VERSION 5.5 ;
NAMESCASESENSITIVE ON ;
BUSBITCHARS "[]" ;
DIVIDERCHAR "/" ;

PROPERTYDEFINITIONS
  LAYER routingPitch REAL ;
END PROPERTYDEFINITIONS

UNITS
  DATABASE MICRONS 1000 ;
END UNITS
MANUFACTURINGGRID 0.01 ;
LAYER POLY1
  TYPE MASTERSLICE ;
END POLY1

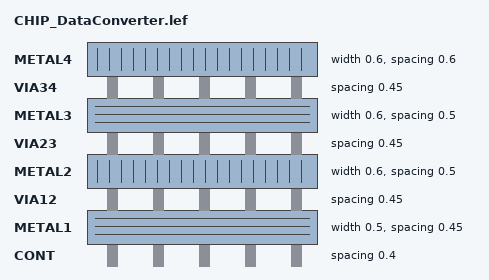
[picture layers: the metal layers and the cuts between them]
LAYER CONT
  TYPE CUT ;
  SPACING 0.4 ;
END CONT

LAYER METAL1
  TYPE ROUTING ;
  DIRECTION HORIZONTAL ;
  PITCH 0 ;
  WIDTH 0.5 ;
  SPACING 0.45 ;
  PROPERTY routingPitch 1.25 ;
END METAL1

LAYER VIA12
  TYPE CUT ;
  SPACING 0.45 ;
END VIA12

LAYER METAL2
  TYPE ROUTING ;
  DIRECTION VERTICAL ;
  PITCH 0 ;
  WIDTH 0.6 ;
  SPACING 0.5 ;
  PROPERTY routingPitch 1.4 ;
END METAL2

LAYER VIA23
  TYPE CUT ;
  SPACING 0.45 ;
END VIA23

LAYER METAL3
  TYPE ROUTING ;
  DIRECTION HORIZONTAL ;
  PITCH 0 ;
  WIDTH 0.6 ;
  SPACING 0.5 ;
  PROPERTY routingPitch 1.25 ;
END METAL3

LAYER VIA34
  TYPE CUT ;
  SPACING 0.45 ;
END VIA34

LAYER METAL4
  TYPE ROUTING ;
  DIRECTION VERTICAL ;
  PITCH 0 ;
  WIDTH 0.6 ;
  SPACING 0.6 ;
  PROPERTY routingPitch 1.4 ;
END METAL4

LAYER OVERLAP
  TYPE OVERLAP ;
END OVERLAP

VIARULE M4_M3 GENERATE
  LAYER METAL3 ;
    ENCLOSURE 0.2 0.2 ;
  LAYER METAL4 ;
    ENCLOSURE 0.15 0.15 ;
  LAYER VIA34 ;
    RECT -0.25 -0.25 0.25 0.25 ;
    SPACING 1 BY 1 ;
END M4_M3

VIARULE M3_M2 GENERATE
  LAYER METAL2 ;
    ENCLOSURE 0.2 0.2 ;
  LAYER METAL3 ;
    ENCLOSURE 0.15 0.15 ;
  LAYER VIA23 ;
    RECT -0.25 -0.25 0.25 0.25 ;
    SPACING 1 BY 1 ;
END M3_M2

VIARULE M2_M1 GENERATE
  LAYER METAL1 ;
    ENCLOSURE 0.2 0.2 ;
  LAYER METAL2 ;
    ENCLOSURE 0.15 0.15 ;
  LAYER VIA12 ;
    RECT -0.25 -0.25 0.25 0.25 ;
    SPACING 1 BY 1 ;
END M2_M1

VIARULE M1_POLY1 GENERATE
  LAYER POLY1 ;
    ENCLOSURE 0.2 0.2 ;
  LAYER METAL1 ;
    ENCLOSURE 0.15 0.15 ;
  LAYER CONT ;
    RECT -0.2 -0.2 0.2 0.2 ;
    SPACING 1 BY 1 ;
END M1_POLY1

VIA M1_POLY1
  LAYER CONT ;
    RECT -0.2 -0.2 0.2 0.2 ;
  LAYER POLY1 ;
    RECT -0.4 -0.4 0.4 0.4 ;
  LAYER METAL1 ;
    RECT -0.35 -0.35 0.35 0.35 ;
END M1_POLY1

VIA M2_M1
  LAYER VIA12 ;
    RECT -0.25 -0.25 0.25 0.25 ;
  LAYER METAL2 ;
    RECT -0.4 -0.4 0.4 0.4 ;
  LAYER METAL1 ;
    RECT -0.45 -0.45 0.45 0.45 ;
END M2_M1

VIA M3_M2
  LAYER VIA23 ;
    RECT -0.25 -0.25 0.25 0.25 ;
  LAYER METAL3 ;
    RECT -0.4 -0.4 0.4 0.4 ;
  LAYER METAL2 ;
    RECT -0.45 -0.45 0.45 0.45 ;
END M3_M2

VIA M4_M3
  LAYER VIA34 ;
    RECT -0.25 -0.25 0.25 0.25 ;
  LAYER METAL4 ;
    RECT -0.4 -0.4 0.4 0.4 ;
  LAYER METAL3 ;
    RECT -0.45 -0.45 0.45 0.45 ;
END M4_M3


MACRO Full_Macro_Edit
  PIN SystemDrainline<1>
    DIRECTION INOUT ;
    USE SIGNAL ;
    PORT
      LAYER METAL3 ;
        RECT 6312.6 1412.6 6314.0 1414.0 ;
    END
  END SystemDrainline<1>
  PIN SystemDrainline<2>
    DIRECTION INOUT ;
    USE SIGNAL ;
    PORT
      LAYER METAL3 ;
        RECT 6312.6 943.6 6314.0 945.0 ;
    END
  END SystemDrainline<2>
  PIN sram_CS_VBIAS
    DIRECTION INOUT ;
    USE SIGNAL ;
    PORT
      LAYER METAL3 ;
        RECT 0.0 2.8 1.4 4.2 ;
    END
  END sram_CS_VBIAS
  PIN drain_pulse_rst
    DIRECTION INOUT ;
    USE SIGNAL ;
    PORT
      LAYER METAL3 ;
        RECT 6312.6 1.4 6314.0 2.8 ;
    END
  END drain_pulse_rst
  PIN fast_ADC_clk
    DIRECTION INOUT ;
    USE SIGNAL ;
    PORT
      LAYER METAL3 ;
        RECT 6312.6 471.8 6314.0 473.2 ;
    END
  END fast_ADC_clk
  PIN peri_spi_slave_RX_DV
    DIRECTION INOUT ;
    USE SIGNAL ;
    PORT
      LAYER METAL3 ;
        RECT 0.0 1412.6 1.4 1414.0 ;
    END
  END peri_spi_slave_RX_DV
  PIN peri_spi_mstr_RX_DV
    DIRECTION INOUT ;
    USE SIGNAL ;
    PORT
      LAYER METAL3 ;
        RECT 0.0 1330.0 1.4 1331.4 ;
    END
  END peri_spi_mstr_RX_DV
  PIN peri_spi_mstr_TX_Ready
    DIRECTION INOUT ;
    USE SIGNAL ;
    PORT
      LAYER METAL3 ;
        RECT 0.0 1247.4 1.4 1248.8 ;
    END
  END peri_spi_mstr_TX_Ready
  PIN peri_spi_mstr_cs_n_3
    DIRECTION INOUT ;
    USE SIGNAL ;
    PORT
      LAYER METAL3 ;
        RECT 0.0 1163.4 1.4 1164.8 ;
    END
  END peri_spi_mstr_cs_n_3
  PIN peri_spi_mstr_cs_n_2
    DIRECTION INOUT ;
    USE SIGNAL ;
    PORT
      LAYER METAL3 ;
        RECT 0.0 1080.8 1.4 1082.2 ;
    END
  END peri_spi_mstr_cs_n_2
  PIN peri_spi_mstr_cs_n_1
    DIRECTION INOUT ;
    USE SIGNAL ;
    PORT
      LAYER METAL3 ;
        RECT 0.0 996.8 1.4 998.2 ;
    END
  END peri_spi_mstr_cs_n_1
  PIN peri_spi_mstr_cs_n_0
    DIRECTION INOUT ;
    USE SIGNAL ;
    PORT
      LAYER METAL3 ;
        RECT 0.0 914.2 1.4 915.6 ;
    END
  END peri_spi_mstr_cs_n_0
  PIN peri_spi_mstr_mosi
    DIRECTION INOUT ;
    USE SIGNAL ;
    PORT
      LAYER METAL3 ;
        RECT 0.0 830.2 1.4 831.6 ;
    END
  END peri_spi_mstr_mosi
  PIN peri_spi_mstr_spiclk
    DIRECTION INOUT ;
    USE SIGNAL ;
    PORT
      LAYER METAL3 ;
        RECT 0.0 664.7 0.6 665.3 ;
    END
  END peri_spi_mstr_spiclk
  PIN peri_spi_slave_miso
    DIRECTION INOUT ;
    USE SIGNAL ;
    PORT
      LAYER METAL3 ;
        RECT 0.0 415.8 1.4 417.2 ;
    END
  END peri_spi_slave_miso
  PIN peri_spi_mstr_miso
    DIRECTION INOUT ;
    USE SIGNAL ;
    PORT
      LAYER METAL3 ;
        RECT 0.0 747.6 1.4 749.0 ;
    END
  END peri_spi_mstr_miso
  PIN peri_spi_slave_cs_n
    DIRECTION INOUT ;
    USE SIGNAL ;
    PORT
      LAYER METAL3 ;
        RECT 0.0 582.4 1.4 583.8 ;
    END
  END peri_spi_slave_cs_n
  PIN peri_spi_slave_mosi
    DIRECTION INOUT ;
    USE SIGNAL ;
    PORT
      LAYER METAL3 ;
        RECT 0.0 498.4 1.4 499.8 ;
    END
  END peri_spi_slave_mosi
  PIN peri_spi_slave_clk
    DIRECTION INOUT ;
    USE SIGNAL ;
    PORT
      LAYER METAL3 ;
        RECT 0.0 331.8 1.4 333.2 ;
    END
  END peri_spi_slave_clk
  PIN peri_spi_cpu_clk
    DIRECTION INOUT ;
    USE SIGNAL ;
    PORT
      LAYER METAL3 ;
        RECT 0.0 249.2 1.4 250.6 ;
    END
  END peri_spi_cpu_clk
  PIN peri_spi_rst
    DIRECTION INOUT ;
    USE SIGNAL ;
    PORT
      LAYER METAL3 ;
        RECT 0.0 165.2 1.4 166.6 ;
    END
  END peri_spi_rst
  PIN peri_use_uP
    DIRECTION INOUT ;
    USE SIGNAL ;
    PORT
      LAYER METAL3 ;
        RECT 0.0 82.6 1.4 84.0 ;
    END
  END peri_use_uP
  PIN irq_acc<12>
    DIRECTION INOUT ;
    USE SIGNAL ;
    PORT
      LAYER METAL2 ;
        RECT 894.6 0.0 896.0 1.4 ;
    END
  END irq_acc<12>
  PIN irq_acc<13>
    DIRECTION INOUT ;
    USE SIGNAL ;
    PORT
      LAYER METAL2 ;
        RECT 834.4 0.0 835.8 1.4 ;
    END
  END irq_acc<13>
  PIN irq<0>
    DIRECTION INOUT ;
    USE SIGNAL ;
    PORT
      LAYER METAL2 ;
        RECT 774.2 0.0 775.6 1.4 ;
    END
  END irq<0>
  PIN irq<1>
    DIRECTION INOUT ;
    USE SIGNAL ;
    PORT
      LAYER METAL2 ;
        RECT 715.4 0.0 716.8 1.4 ;
    END
  END irq<1>
  PIN irq<2>
    DIRECTION INOUT ;
    USE SIGNAL ;
    PORT
      LAYER METAL2 ;
        RECT 655.2 0.0 656.6 1.4 ;
    END
  END irq<2>
  PIN irq<3>
    DIRECTION INOUT ;
    USE SIGNAL ;
    PORT
      LAYER METAL2 ;
        RECT 596.4 0.0 597.8 1.4 ;
    END
  END irq<3>
  PIN irq<4>
    DIRECTION INOUT ;
    USE SIGNAL ;
    PORT
      LAYER METAL2 ;
        RECT 536.2 0.0 537.6 1.4 ;
    END
  END irq<4>
  PIN irq<5>
    DIRECTION INOUT ;
    USE SIGNAL ;
    PORT
      LAYER METAL2 ;
        RECT 477.4 0.0 478.8 1.4 ;
    END
  END irq<5>
  PIN irq<6>
    DIRECTION INOUT ;
    USE SIGNAL ;
    PORT
      LAYER METAL2 ;
        RECT 417.2 0.0 418.6 1.4 ;
    END
  END irq<6>
  PIN irq<7>
    DIRECTION INOUT ;
    USE SIGNAL ;
    PORT
      LAYER METAL2 ;
        RECT 358.4 0.0 359.8 1.4 ;
    END
  END irq<7>
  PIN irq<8>
    DIRECTION INOUT ;
    USE SIGNAL ;
    PORT
      LAYER METAL2 ;
        RECT 298.2 0.0 299.6 1.4 ;
    END
  END irq<8>
  PIN irq<9>
    DIRECTION INOUT ;
    USE SIGNAL ;
    PORT
      LAYER METAL2 ;
        RECT 239.4 0.0 240.8 1.4 ;
    END
  END irq<9>
  PIN irq<10>
    DIRECTION INOUT ;
    USE SIGNAL ;
    PORT
      LAYER METAL2 ;
        RECT 179.2 0.0 180.6 1.4 ;
    END
  END irq<10>
  PIN irq<11>
    DIRECTION INOUT ;
    USE SIGNAL ;
    PORT
      LAYER METAL2 ;
        RECT 119.0 0.0 120.4 1.4 ;
    END
  END irq<11>
  PIN irq<12>
    DIRECTION INOUT ;
    USE SIGNAL ;
    PORT
      LAYER METAL2 ;
        RECT 60.2 0.0 61.6 1.4 ;
    END
  END irq<12>
  PIN irq<13>
    DIRECTION INOUT ;
    USE SIGNAL ;
    PORT
      LAYER METAL2 ;
        RECT 1.4 0.0 2.8 1.4 ;
    END
  END irq<13>
  PIN irq_acc<1>
    DIRECTION INOUT ;
    USE SIGNAL ;
    PORT
      LAYER METAL2 ;
        RECT 1548.4 0.0 1549.8 1.4 ;
    END
  END irq_acc<1>
  PIN irq_acc<2>
    DIRECTION INOUT ;
    USE SIGNAL ;
    PORT
      LAYER METAL2 ;
        RECT 1489.6 0.0 1491.0 1.4 ;
    END
  END irq_acc<2>
  PIN irq_acc<3>
    DIRECTION INOUT ;
    USE SIGNAL ;
    PORT
      LAYER METAL2 ;
        RECT 1429.4 0.0 1430.8 1.4 ;
    END
  END irq_acc<3>
  PIN irq_acc<4>
    DIRECTION INOUT ;
    USE SIGNAL ;
    PORT
      LAYER METAL2 ;
        RECT 1370.6 0.0 1372.0 1.4 ;
    END
  END irq_acc<4>
  PIN irq_acc<5>
    DIRECTION INOUT ;
    USE SIGNAL ;
    PORT
      LAYER METAL2 ;
        RECT 1310.4 0.0 1311.8 1.4 ;
    END
  END irq_acc<5>
  PIN irq_acc<6>
    DIRECTION INOUT ;
    USE SIGNAL ;
    PORT
      LAYER METAL2 ;
        RECT 1251.6 0.0 1253.0 1.4 ;
    END
  END irq_acc<6>
  PIN irq_acc<7>
    DIRECTION INOUT ;
    USE SIGNAL ;
    PORT
      LAYER METAL2 ;
        RECT 1191.4 0.0 1192.8 1.4 ;
    END
  END irq_acc<7>
  PIN irq_acc<8>
    DIRECTION INOUT ;
    USE SIGNAL ;
    PORT
      LAYER METAL2 ;
        RECT 1132.6 0.0 1134.0 1.4 ;
    END
  END irq_acc<8>
  PIN irq_acc<9>
    DIRECTION INOUT ;
    USE SIGNAL ;
    PORT
      LAYER METAL2 ;
        RECT 1072.4 0.0 1073.8 1.4 ;
    END
  END irq_acc<9>
  PIN irq_acc<10>
    DIRECTION INOUT ;
    USE SIGNAL ;
    PORT
      LAYER METAL2 ;
        RECT 1013.6 0.0 1015.0 1.4 ;
    END
  END irq_acc<10>
  PIN irq_acc<11>
    DIRECTION INOUT ;
    USE SIGNAL ;
    PORT
      LAYER METAL2 ;
        RECT 953.4 0.0 954.8 1.4 ;
    END
  END irq_acc<11>
  PIN irq_acc<0>
    DIRECTION INOUT ;
    USE SIGNAL ;
    PORT
      LAYER METAL2 ;
        RECT 1608.6 0.0 1610.0 1.4 ;
    END
  END irq_acc<0>
  PIN mmio_reg_4_vinj_out<1>
    DIRECTION INOUT ;
    USE SIGNAL ;
    PORT
      LAYER METAL2 ;
        RECT 1906.8 0.0 1908.2 1.4 ;
    END
  END mmio_reg_4_vinj_out<1>
  PIN mmio_reg_4_vinj_out<2>
    DIRECTION INOUT ;
    USE SIGNAL ;
    PORT
      LAYER METAL2 ;
        RECT 1846.6 0.0 1848.0 1.4 ;
    END
  END mmio_reg_4_vinj_out<2>
  PIN mmio_reg_4_vinj_out<3>
    DIRECTION INOUT ;
    USE SIGNAL ;
    PORT
      LAYER METAL2 ;
        RECT 1787.8 0.0 1789.2 1.4 ;
    END
  END mmio_reg_4_vinj_out<3>
  PIN mmio_reg_4_vinj_out<4>
    DIRECTION INOUT ;
    USE SIGNAL ;
    PORT
      LAYER METAL2 ;
        RECT 1727.6 0.0 1729.0 1.4 ;
    END
  END mmio_reg_4_vinj_out<4>
  PIN mmio_reg_4_vinj_out<5>
    DIRECTION INOUT ;
    USE SIGNAL ;
    PORT
      LAYER METAL2 ;
        RECT 1668.8 0.0 1670.2 1.4 ;
    END
  END mmio_reg_4_vinj_out<5>
  PIN mmio_reg_4_vinj_out<0>
    DIRECTION INOUT ;
    USE SIGNAL ;
    PORT
      LAYER METAL2 ;
        RECT 1965.6 0.0 1967.0 1.4 ;
    END
  END mmio_reg_4_vinj_out<0>
  PIN mmio_reg_3_vinj_out<10>
    DIRECTION INOUT ;
    USE SIGNAL ;
    PORT
      LAYER METAL2 ;
        RECT 2322.6 0.0 2324.0 1.4 ;
    END
  END mmio_reg_3_vinj_out<10>
  PIN mmio_reg_3_vinj_out<11>
    DIRECTION INOUT ;
    USE SIGNAL ;
    PORT
      LAYER METAL2 ;
        RECT 2263.8 0.0 2265.2 1.4 ;
    END
  END mmio_reg_3_vinj_out<11>
  PIN mmio_reg_3_vinj_out<12>
    DIRECTION INOUT ;
    USE SIGNAL ;
    PORT
      LAYER METAL2 ;
        RECT 2203.6 0.0 2205.0 1.4 ;
    END
  END mmio_reg_3_vinj_out<12>
  PIN mmio_reg_3_vinj_out<13>
    DIRECTION INOUT ;
    USE SIGNAL ;
    PORT
      LAYER METAL2 ;
        RECT 2144.8 0.0 2146.2 1.4 ;
    END
  END mmio_reg_3_vinj_out<13>
  PIN mmio_reg_3_vinj_out<14>
    DIRECTION INOUT ;
    USE SIGNAL ;
    PORT
      LAYER METAL2 ;
        RECT 2084.6 0.0 2086.0 1.4 ;
    END
  END mmio_reg_3_vinj_out<14>
  PIN mmio_reg_3_vinj_out<15>
    DIRECTION INOUT ;
    USE SIGNAL ;
    PORT
      LAYER METAL2 ;
        RECT 2025.8 0.0 2027.2 1.4 ;
    END
  END mmio_reg_3_vinj_out<15>
  PIN mmio_reg_1_out<0>
    DIRECTION INOUT ;
    USE SIGNAL ;
    PORT
      LAYER METAL2 ;
        RECT 2501.8 0.0 2503.2 1.4 ;
    END
  END mmio_reg_1_out<0>
  PIN mmio_reg_1_out<1>
    DIRECTION INOUT ;
    USE SIGNAL ;
    PORT
      LAYER METAL2 ;
        RECT 2562.0 0.0 2563.4 1.4 ;
    END
  END mmio_reg_1_out<1>
  PIN mmio_reg_in_5<9>
    DIRECTION INOUT ;
    USE SIGNAL ;
    PORT
      LAYER METAL2 ;
        RECT 2977.8 0.0 2979.2 1.4 ;
    END
  END mmio_reg_in_5<9>
  PIN mmio_reg_in_5<10>
    DIRECTION INOUT ;
    USE SIGNAL ;
    PORT
      LAYER METAL2 ;
        RECT 2919.0 0.0 2920.4 1.4 ;
    END
  END mmio_reg_in_5<10>
  PIN mmio_reg_in_5<11>
    DIRECTION INOUT ;
    USE SIGNAL ;
    PORT
      LAYER METAL2 ;
        RECT 2858.8 0.0 2860.2 1.4 ;
    END
  END mmio_reg_in_5<11>
  PIN mmio_reg_in_5<12>
    DIRECTION INOUT ;
    USE SIGNAL ;
    PORT
      LAYER METAL2 ;
        RECT 2800.0 0.0 2801.4 1.4 ;
    END
  END mmio_reg_in_5<12>
  PIN mmio_reg_in_5<13>
    DIRECTION INOUT ;
    USE SIGNAL ;
    PORT
      LAYER METAL2 ;
        RECT 2739.8 0.0 2741.2 1.4 ;
    END
  END mmio_reg_in_5<13>
  PIN mmio_reg_in_5<14>
    DIRECTION INOUT ;
    USE SIGNAL ;
    PORT
      LAYER METAL2 ;
        RECT 2681.0 0.0 2682.4 1.4 ;
    END
  END mmio_reg_in_5<14>
  PIN mmio_reg_in_5<15>
    DIRECTION INOUT ;
    USE SIGNAL ;
    PORT
      LAYER METAL2 ;
        RECT 2620.8 0.0 2622.2 1.4 ;
    END
  END mmio_reg_in_5<15>
  PIN mmio_reg_in_5<2>
    DIRECTION INOUT ;
    USE SIGNAL ;
    PORT
      LAYER METAL2 ;
        RECT 3395.0 0.0 3396.4 1.4 ;
    END
  END mmio_reg_in_5<2>
  PIN mmio_reg_in_5<3>
    DIRECTION INOUT ;
    USE SIGNAL ;
    PORT
      LAYER METAL2 ;
        RECT 3336.2 0.0 3337.6 1.4 ;
    END
  END mmio_reg_in_5<3>
  PIN mmio_reg_in_5<4>
    DIRECTION INOUT ;
    USE SIGNAL ;
    PORT
      LAYER METAL2 ;
        RECT 3276.0 0.0 3277.4 1.4 ;
    END
  END mmio_reg_in_5<4>
  PIN mmio_reg_in_5<5>
    DIRECTION INOUT ;
    USE SIGNAL ;
    PORT
      LAYER METAL2 ;
        RECT 3217.2 0.0 3218.6 1.4 ;
    END
  END mmio_reg_in_5<5>
  PIN mmio_reg_in_5<6>
    DIRECTION INOUT ;
    USE SIGNAL ;
    PORT
      LAYER METAL2 ;
        RECT 3157.0 0.0 3158.4 1.4 ;
    END
  END mmio_reg_in_5<6>
  PIN mmio_reg_in_5<7>
    DIRECTION INOUT ;
    USE SIGNAL ;
    PORT
      LAYER METAL2 ;
        RECT 3096.8 0.0 3098.2 1.4 ;
    END
  END mmio_reg_in_5<7>
  PIN mmio_reg_in_5<8>
    DIRECTION INOUT ;
    USE SIGNAL ;
    PORT
      LAYER METAL2 ;
        RECT 3038.0 0.0 3039.4 1.4 ;
    END
  END mmio_reg_in_5<8>
  PIN mmio_reg_10<11>
    DIRECTION INOUT ;
    USE SIGNAL ;
    PORT
      LAYER METAL2 ;
        RECT 3812.2 0.0 3813.6 1.4 ;
    END
  END mmio_reg_10<11>
  PIN mmio_reg_10<12>
    DIRECTION INOUT ;
    USE SIGNAL ;
    PORT
      LAYER METAL2 ;
        RECT 3752.0 0.0 3753.4 1.4 ;
    END
  END mmio_reg_10<12>
  PIN mmio_reg_10<13>
    DIRECTION INOUT ;
    USE SIGNAL ;
    PORT
      LAYER METAL2 ;
        RECT 3693.2 0.0 3694.6 1.4 ;
    END
  END mmio_reg_10<13>
  PIN mmio_reg_10<14>
    DIRECTION INOUT ;
    USE SIGNAL ;
    PORT
      LAYER METAL2 ;
        RECT 3633.0 0.0 3634.4 1.4 ;
    END
  END mmio_reg_10<14>
  PIN mmio_reg_10<15>
    DIRECTION INOUT ;
    USE SIGNAL ;
    PORT
      LAYER METAL2 ;
        RECT 3574.2 0.0 3575.6 1.4 ;
    END
  END mmio_reg_10<15>
  PIN mmio_reg_in_5<0>
    DIRECTION INOUT ;
    USE SIGNAL ;
    PORT
      LAYER METAL2 ;
        RECT 3514.0 0.0 3515.4 1.4 ;
    END
  END mmio_reg_in_5<0>
  PIN mmio_reg_in_5<1>
    DIRECTION INOUT ;
    USE SIGNAL ;
    PORT
      LAYER METAL2 ;
        RECT 3455.2 0.0 3456.6 1.4 ;
    END
  END mmio_reg_in_5<1>
  PIN mmio_reg_10<4>
    DIRECTION INOUT ;
    USE SIGNAL ;
    PORT
      LAYER METAL2 ;
        RECT 4229.4 0.0 4230.8 1.4 ;
    END
  END mmio_reg_10<4>
  PIN mmio_reg_10<5>
    DIRECTION INOUT ;
    USE SIGNAL ;
    PORT
      LAYER METAL2 ;
        RECT 4169.2 0.0 4170.6 1.4 ;
    END
  END mmio_reg_10<5>
  PIN mmio_reg_10<6>
    DIRECTION INOUT ;
    USE SIGNAL ;
    PORT
      LAYER METAL2 ;
        RECT 4110.4 0.0 4111.8 1.4 ;
    END
  END mmio_reg_10<6>
  PIN mmio_reg_10<7>
    DIRECTION INOUT ;
    USE SIGNAL ;
    PORT
      LAYER METAL2 ;
        RECT 4050.2 0.0 4051.6 1.4 ;
    END
  END mmio_reg_10<7>
  PIN mmio_reg_10<8>
    DIRECTION INOUT ;
    USE SIGNAL ;
    PORT
      LAYER METAL2 ;
        RECT 3991.4 0.0 3992.8 1.4 ;
    END
  END mmio_reg_10<8>
  PIN mmio_reg_10<9>
    DIRECTION INOUT ;
    USE SIGNAL ;
    PORT
      LAYER METAL2 ;
        RECT 3931.2 0.0 3932.6 1.4 ;
    END
  END mmio_reg_10<9>
  PIN mmio_reg_10<10>
    DIRECTION INOUT ;
    USE SIGNAL ;
    PORT
      LAYER METAL2 ;
        RECT 3871.0 0.0 3872.4 1.4 ;
    END
  END mmio_reg_10<10>
  PIN mmio_reg_10<0>
    DIRECTION INOUT ;
    USE SIGNAL ;
    PORT
      LAYER METAL2 ;
        RECT 4467.4 0.0 4468.8 1.4 ;
    END
  END mmio_reg_10<0>
  PIN mmio_reg_10<1>
    DIRECTION INOUT ;
    USE SIGNAL ;
    PORT
      LAYER METAL2 ;
        RECT 4407.2 0.0 4408.6 1.4 ;
    END
  END mmio_reg_10<1>
  PIN mmio_reg_10<2>
    DIRECTION INOUT ;
    USE SIGNAL ;
    PORT
      LAYER METAL2 ;
        RECT 4348.4 0.0 4349.8 1.4 ;
    END
  END mmio_reg_10<2>
  PIN mmio_reg_10<3>
    DIRECTION INOUT ;
    USE SIGNAL ;
    PORT
      LAYER METAL2 ;
        RECT 4288.2 0.0 4289.6 1.4 ;
    END
  END mmio_reg_10<3>
  PIN mmio_reg_2_out_b15
    DIRECTION INOUT ;
    USE SIGNAL ;
    PORT
      LAYER METAL2 ;
        RECT 2382.8 0.0 2384.2 1.4 ;
    END
  END mmio_reg_2_out_b15
  PIN mmio_reg_9_out_b15
    DIRECTION INOUT ;
    USE SIGNAL ;
    PORT
      LAYER METAL2 ;
        RECT 2443.0 0.0 2444.4 1.4 ;
    END
  END mmio_reg_9_out_b15
  PIN Signal_DAC_out[0]
    DIRECTION INOUT ;
    USE SIGNAL ;
    PORT
      LAYER METAL2 ;
        RECT 5360.6 0.0 5362.0 1.4 ;
    END
  END Signal_DAC_out[0]
  PIN Signal_DAC_out[1]
    DIRECTION INOUT ;
    USE SIGNAL ;
    PORT
      LAYER METAL2 ;
        RECT 5300.4 0.0 5301.8 1.4 ;
    END
  END Signal_DAC_out[1]
  PIN Signal_DAC_out[2]
    DIRECTION INOUT ;
    USE SIGNAL ;
    PORT
      LAYER METAL2 ;
        RECT 5241.6 0.0 5243.0 1.4 ;
    END
  END Signal_DAC_out[2]
  PIN Signal_DAC_out[3]
    DIRECTION INOUT ;
    USE SIGNAL ;
    PORT
      LAYER METAL2 ;
        RECT 5181.4 0.0 5182.8 1.4 ;
    END
  END Signal_DAC_out[3]
  PIN Signal_DAC_out[4]
    DIRECTION INOUT ;
    USE SIGNAL ;
    PORT
      LAYER METAL2 ;
        RECT 5122.6 0.0 5124.0 1.4 ;
    END
  END Signal_DAC_out[4]
  PIN Signal_ADC_inp[0]
    DIRECTION INOUT ;
    USE SIGNAL ;
    PORT
      LAYER METAL2 ;
        RECT 5717.6 0.0 5719.0 1.4 ;
    END
  END Signal_ADC_inp[0]
  PIN Signal_ADC_inp[1]
    DIRECTION INOUT ;
    USE SIGNAL ;
    PORT
      LAYER METAL2 ;
        RECT 5658.8 0.0 5660.2 1.4 ;
    END
  END Signal_ADC_inp[1]
  PIN Signal_ADC_inp[2]
    DIRECTION INOUT ;
    USE SIGNAL ;
    PORT
      LAYER METAL2 ;
        RECT 5598.6 0.0 5600.0 1.4 ;
    END
  END Signal_ADC_inp[2]
  PIN Signal_ADC_inp[3]
    DIRECTION INOUT ;
    USE SIGNAL ;
    PORT
      LAYER METAL2 ;
        RECT 5539.8 0.0 5541.2 1.4 ;
    END
  END Signal_ADC_inp[3]
  PIN Signal_ADC_inp[4]
    DIRECTION INOUT ;
    USE SIGNAL ;
    PORT
      LAYER METAL2 ;
        RECT 5479.6 0.0 5481.0 1.4 ;
    END
  END Signal_ADC_inp[4]
  PIN Signal_ADC_inp[5]
    DIRECTION INOUT ;
    USE SIGNAL ;
    PORT
      LAYER METAL2 ;
        RECT 5419.4 0.0 5420.8 1.4 ;
    END
  END Signal_ADC_inp[5]
  PIN VGPROG_IO
    DIRECTION INOUT ;
    USE SIGNAL ;
    PORT
      LAYER METAL2 ;
        RECT 5955.6 0.0 5957.0 1.4 ;
    END
  END VGPROG_IO
  PIN VTUN_AM
    DIRECTION INOUT ;
    USE SIGNAL ;
    PORT
      LAYER METAL2 ;
        RECT 6074.6 0.0 6076.0 1.4 ;
    END
  END VTUN_AM
  PIN AVDD_AM
    DIRECTION INOUT ;
    USE SIGNAL ;
    PORT
      LAYER METAL2 ;
        RECT 6193.6 0.0 6195.0 1.4 ;
    END
  END AVDD_AM
  PIN V_IO
    DIRECTION INOUT ;
    USE SIGNAL ;
    PORT
      LAYER METAL2 ;
        RECT 4526.2 0.0 4527.6 1.4 ;
    END
  END V_IO
  PIN VG_IO
    DIRECTION INOUT ;
    USE SIGNAL ;
    PORT
      LAYER METAL2 ;
        RECT 4586.4 0.0 4587.8 1.4 ;
    END
  END VG_IO
  PIN VGRUN
    DIRECTION INOUT ;
    USE SIGNAL ;
    PORT
      LAYER METAL2 ;
        RECT 4645.2 0.0 4646.6 1.4 ;
    END
  END VGRUN
  PIN VD_IO
    DIRECTION INOUT ;
    USE SIGNAL ;
    PORT
      LAYER METAL2 ;
        RECT 4705.4 0.0 4706.8 1.4 ;
    END
  END VD_IO
  PIN I_IO
    DIRECTION INOUT ;
    USE SIGNAL ;
    PORT
      LAYER METAL2 ;
        RECT 4765.6 0.0 4767.0 1.4 ;
    END
  END I_IO
  PIN Debug_IO
    DIRECTION INOUT ;
    USE SIGNAL ;
    PORT
      LAYER METAL2 ;
        RECT 4824.4 0.0 4825.8 1.4 ;
    END
  END Debug_IO
  PIN Cal_Vin
    DIRECTION INOUT ;
    USE SIGNAL ;
    PORT
      LAYER METAL2 ;
        RECT 4884.6 0.0 4886.0 1.4 ;
    END
  END Cal_Vin
  PIN Cal_IO
    DIRECTION INOUT ;
    USE SIGNAL ;
    PORT
      LAYER METAL2 ;
        RECT 4943.4 0.0 4944.8 1.4 ;
    END
  END Cal_IO
  PIN Bias_Trim
    DIRECTION INOUT ;
    USE SIGNAL ;
    PORT
      LAYER METAL2 ;
        RECT 5003.6 0.0 5005.0 1.4 ;
    END
  END Bias_Trim
  PIN ADC_Trim
    DIRECTION INOUT ;
    USE SIGNAL ;
    PORT
      LAYER METAL2 ;
        RECT 5062.4 0.0 5063.8 1.4 ;
    END
  END ADC_Trim
  PIN run
    DIRECTION INOUT ;
    USE SIGNAL ;
    PORT
      LAYER METAL2 ;
        RECT 5777.8 0.0 5779.2 1.4 ;
    END
  END run
  PIN prog
    DIRECTION INOUT ;
    USE SIGNAL ;
    PORT
      LAYER METAL2 ;
        RECT 5836.6 0.0 5838.0 1.4 ;
    END
  END prog
  PIN fgmem_CS_VBIAS
    DIRECTION INOUT ;
    USE SIGNAL ;
    PORT
      LAYER METAL2 ;
        RECT 5896.8 0.0 5898.2 1.4 ;
    END
  END fgmem_CS_VBIAS
  PIN VTUN_fgmem
    DIRECTION INOUT ;
    USE SIGNAL ;
    PORT
      LAYER METAL2 ;
        RECT 6015.8 0.0 6017.2 1.4 ;
    END
  END VTUN_fgmem
  PIN VINJ
    DIRECTION INOUT ;
    USE SIGNAL ;
    PORT
      LAYER METAL2 ;
        RECT 6134.8 0.0 6136.2 1.4 ;
    END
  END VINJ
  PIN GND
    DIRECTION INOUT ;
    USE SIGNAL ;
    PORT
      LAYER METAL2 ;
        RECT 6253.8 0.0 6255.2 1.4 ;
    END
  END GND
  PIN DVDD
    DIRECTION INOUT ;
    USE SIGNAL ;
    PORT
      LAYER METAL2 ;
        RECT 6311.2 0.0 6312.6 1.4 ;
    END
  END DVDD
  PIN scan_out2
    DIRECTION INOUT ;
    USE SIGNAL ;
    PORT
      LAYER METAL2 ;
        RECT 3682.0 1414.0 3683.4 1415.4 ;
    END
  END scan_out2
  PIN scan_in2
    DIRECTION INOUT ;
    USE SIGNAL ;
    PORT
      LAYER METAL2 ;
        RECT 3155.6 1414.0 3157.0 1415.4 ;
    END
  END scan_in2
  PIN scan_out1
    DIRECTION INOUT ;
    USE SIGNAL ;
    PORT
      LAYER METAL2 ;
        RECT 3418.8 1414.0 3420.2 1415.4 ;
    END
  END scan_out1
  PIN scan_in1
    DIRECTION INOUT ;
    USE SIGNAL ;
    PORT
      LAYER METAL2 ;
        RECT 2892.4 1414.0 2893.8 1415.4 ;
    END
  END scan_in1
  PIN wkup
    DIRECTION INOUT ;
    USE SIGNAL ;
    PORT
      LAYER METAL2 ;
        RECT 2629.2 1414.0 2630.6 1415.4 ;
    END
  END wkup
  PIN scan_mode
    DIRECTION INOUT ;
    USE SIGNAL ;
    PORT
      LAYER METAL2 ;
        RECT 2366.0 1414.0 2367.4 1415.4 ;
    END
  END scan_mode
  PIN scan_enable
    DIRECTION INOUT ;
    USE SIGNAL ;
    PORT
      LAYER METAL2 ;
        RECT 2104.2 1414.0 2105.6 1415.4 ;
    END
  END scan_enable
  PIN reset_n
    DIRECTION INOUT ;
    USE SIGNAL ;
    PORT
      LAYER METAL2 ;
        RECT 1841.0 1414.0 1842.4 1415.4 ;
    END
  END reset_n
  PIN nmi
    DIRECTION INOUT ;
    USE SIGNAL ;
    PORT
      LAYER METAL2 ;
        RECT 1577.8 1414.0 1579.2 1415.4 ;
    END
  END nmi
  PIN lfxt_clk
    DIRECTION INOUT ;
    USE SIGNAL ;
    PORT
      LAYER METAL2 ;
        RECT 1314.61 1414.0 1316.0 1415.4 ;
    END
  END lfxt_clk
  PIN dco_clk
    DIRECTION INOUT ;
    USE SIGNAL ;
    PORT
      LAYER METAL2 ;
        RECT 1051.4 1414.0 1052.8 1415.4 ;
    END
  END dco_clk
  PIN dbg_uart_rxd
    DIRECTION INOUT ;
    USE SIGNAL ;
    PORT
      LAYER METAL2 ;
        RECT 525.0 1414.0 526.4 1415.4 ;
    END
  END dbg_uart_rxd
  PIN dbg_en
    DIRECTION INOUT ;
    USE SIGNAL ;
    PORT
      LAYER METAL2 ;
        RECT 261.8 1414.0 263.2 1415.4 ;
    END
  END dbg_en
  PIN cpu_en
    DIRECTION INOUT ;
    USE SIGNAL ;
    PORT
      LAYER METAL2 ;
        RECT 1.4 1414.0 2.8 1415.4 ;
    END
  END cpu_en
  PIN smclk_en
    DIRECTION INOUT ;
    USE SIGNAL ;
    PORT
      LAYER METAL2 ;
        RECT 6309.8 1414.0 6311.2 1415.4 ;
    END
  END smclk_en
  PIN smclk
    DIRECTION INOUT ;
    USE SIGNAL ;
    PORT
      LAYER METAL2 ;
        RECT 6049.4 1414.0 6050.8 1415.4 ;
    END
  END smclk
  PIN mclk
    DIRECTION INOUT ;
    USE SIGNAL ;
    PORT
      LAYER METAL2 ;
        RECT 5786.2 1414.0 5787.6 1415.4 ;
    END
  END mclk
  PIN lfxt_wkup
    DIRECTION INOUT ;
    USE SIGNAL ;
    PORT
      LAYER METAL2 ;
        RECT 5523.0 1414.0 5524.4 1415.4 ;
    END
  END lfxt_wkup
  PIN lfxt_enable
    DIRECTION INOUT ;
    USE SIGNAL ;
    PORT
      LAYER METAL2 ;
        RECT 5259.8 1414.0 5261.2 1415.4 ;
    END
  END lfxt_enable
  PIN dco_wkup
    DIRECTION INOUT ;
    USE SIGNAL ;
    PORT
      LAYER METAL2 ;
        RECT 4996.6 1414.0 4998.0 1415.4 ;
    END
  END dco_wkup
  PIN dco_enable
    DIRECTION INOUT ;
    USE SIGNAL ;
    PORT
      LAYER METAL2 ;
        RECT 4733.4 1414.0 4734.8 1415.4 ;
    END
  END dco_enable
  PIN dbg_uart_txd
    DIRECTION INOUT ;
    USE SIGNAL ;
    PORT
      LAYER METAL2 ;
        RECT 788.2 1414.0 789.6 1415.4 ;
    END
  END dbg_uart_txd
  PIN dbg_freeze
    DIRECTION INOUT ;
    USE SIGNAL ;
    PORT
      LAYER METAL2 ;
        RECT 4470.2 1414.0 4471.6 1415.4 ;
    END
  END dbg_freeze
  PIN aclk_en
    DIRECTION INOUT ;
    USE SIGNAL ;
    PORT
      LAYER METAL2 ;
        RECT 4208.4 1414.0 4209.8 1415.4 ;
    END
  END aclk_en
  PIN aclk
    DIRECTION INOUT ;
    USE SIGNAL ;
    PORT
      LAYER METAL2 ;
        RECT 3945.2 1414.0 3946.6 1415.4 ;
    END
  END aclk
END Full_Macro_Edit

MACRO QDAC_synth
  PIN n_VGRUN
    DIRECTION INOUT ;
    USE SIGNAL ;
    PORT
      LAYER METAL3 ;
        RECT 55.3 246.7 56.7 249.5 ;
    END
  END n_VGRUN
  PIN w_GateB<0>
    DIRECTION INOUT ;
    USE SIGNAL ;
    PORT
      LAYER METAL3 ;
        RECT 0.0 234.1 2.8 235.5 ;
    END
  END w_GateB<0>
  PIN w_GateB<1>
    DIRECTION INOUT ;
    USE SIGNAL ;
    PORT
      LAYER METAL3 ;
        RECT 0.0 220.1 2.8 221.5 ;
    END
  END w_GateB<1>
  PIN n_Code<4>
    DIRECTION INOUT ;
    USE SIGNAL ;
    PORT
      LAYER METAL3 ;
        RECT 167.3 246.7 168.7 249.5 ;
    END
  END n_Code<4>
  PIN n_Code<0>
    DIRECTION INOUT ;
    USE SIGNAL ;
    PORT
      LAYER METAL3 ;
        RECT 111.3 246.7 112.7 249.5 ;
    END
  END n_Code<0>
  PIN n_VGPROG
    DIRECTION INOUT ;
    USE SIGNAL ;
    PORT
      LAYER METAL3 ;
        RECT 41.3 246.7 42.7 249.5 ;
    END
  END n_VGPROG
  PIN s_vinj
    DIRECTION INOUT ;
    USE SIGNAL ;
    PORT
      LAYER METAL3 ;
        RECT 192.41 0.0 193.81 2.8 ;
    END
  END s_vinj
  PIN n_Code<2>
    DIRECTION INOUT ;
    USE SIGNAL ;
    PORT
      LAYER METAL3 ;
        RECT 139.3 246.7 140.7 249.5 ;
    END
  END n_Code<2>
  PIN n_Code<3>
    DIRECTION INOUT ;
    USE SIGNAL ;
    PORT
      LAYER METAL3 ;
        RECT 153.3 246.7 154.7 249.5 ;
    END
  END n_Code<3>
  PIN w_DrainEnable
    DIRECTION INOUT ;
    USE SIGNAL ;
    PORT
      LAYER METAL3 ;
        RECT 0.0 150.1 2.8 151.5 ;
    END
  END w_DrainEnable
  PIN n_Code<1>
    DIRECTION INOUT ;
    USE SIGNAL ;
    PORT
      LAYER METAL3 ;
        RECT 125.3 246.7 126.7 249.5 ;
    END
  END n_Code<1>
  PIN n_RST
    DIRECTION INOUT ;
    USE SIGNAL ;
    PORT
      LAYER METAL3 ;
        RECT 97.3 246.7 98.7 249.5 ;
    END
  END n_RST
  PIN n_gnd
    DIRECTION INOUT ;
    USE SIGNAL ;
    PORT
      LAYER METAL3 ;
        RECT 206.41 246.7 207.81 249.5 ;
    END
  END n_gnd
  PIN s_gnd
    DIRECTION INOUT ;
    USE SIGNAL ;
    PORT
      LAYER METAL3 ;
        RECT 206.41 0.0 207.81 2.8 ;
    END
  END s_gnd
  PIN s_Run_Drainline
    DIRECTION INOUT ;
    USE SIGNAL ;
    PORT
      LAYER METAL3 ;
        RECT 13.3 0.0 14.7 2.8 ;
    END
  END s_Run_Drainline
  PIN s_Vout
    DIRECTION INOUT ;
    USE SIGNAL ;
    PORT
      LAYER METAL3 ;
        RECT 41.3 0.0 42.7 2.8 ;
    END
  END s_Vout
  PIN n_vinj
    DIRECTION INOUT ;
    USE SIGNAL ;
    PORT
      LAYER METAL3 ;
        RECT 192.41 246.7 193.81 249.5 ;
    END
  END n_vinj
  PIN w_DrainB<1>
    DIRECTION INOUT ;
    USE SIGNAL ;
    PORT
      LAYER METAL3 ;
        RECT 0.0 192.1 2.8 193.5 ;
    END
  END w_DrainB<1>
  PIN w_DrainB<3>
    DIRECTION INOUT ;
    USE SIGNAL ;
    PORT
      LAYER METAL3 ;
        RECT 0.0 164.1 2.8 165.5 ;
    END
  END w_DrainB<3>
  PIN s_Prog_Drainline
    DIRECTION INOUT ;
    USE SIGNAL ;
    PORT
      LAYER METAL3 ;
        RECT 27.3 0.0 28.7 2.8 ;
    END
  END s_Prog_Drainline
  PIN n_Run
    DIRECTION INOUT ;
    USE SIGNAL ;
    PORT
      LAYER METAL3 ;
        RECT 27.3 246.7 28.7 249.5 ;
    END
  END n_Run
  PIN w_DrainB<2>
    DIRECTION INOUT ;
    USE SIGNAL ;
    PORT
      LAYER METAL3 ;
        RECT 0.0 178.1 2.8 179.5 ;
    END
  END w_DrainB<2>
  PIN n_VTUN
    DIRECTION INOUT ;
    USE SIGNAL ;
    PORT
      LAYER METAL3 ;
        RECT 69.3 246.7 70.7 249.5 ;
    END
  END n_VTUN
  PIN n_GateEnable
    DIRECTION INOUT ;
    USE SIGNAL ;
    PORT
      LAYER METAL3 ;
        RECT 83.3 246.7 84.7 249.5 ;
    END
  END n_GateEnable
  PIN n_avdd
    DIRECTION INOUT ;
    USE SIGNAL ;
    PORT
      LAYER METAL3 ;
        RECT 220.41 246.7 221.81 249.5 ;
    END
  END n_avdd
  PIN s_avdd
    DIRECTION INOUT ;
    USE SIGNAL ;
    PORT
      LAYER METAL3 ;
        RECT 220.41 0.0 221.81 2.8 ;
    END
  END s_avdd
  PIN n_Prog
    DIRECTION INOUT ;
    USE SIGNAL ;
    PORT
      LAYER METAL3 ;
        RECT 13.3 246.7 14.7 249.5 ;
    END
  END n_Prog
  PIN w_DrainB<0>
    DIRECTION INOUT ;
    USE SIGNAL ;
    PORT
      LAYER METAL3 ;
        RECT 0.0 206.1 2.8 207.5 ;
    END
  END w_DrainB<0>
END QDAC_synth

MACRO RampADC_synth
  PIN n_gnd
    DIRECTION INOUT ;
    USE SIGNAL ;
    PORT
      LAYER METAL3 ;
        RECT 274.04 141.6 275.44 144.4 ;
    END
  END n_gnd
  PIN s_gnd
    DIRECTION INOUT ;
    USE SIGNAL ;
    PORT
      LAYER METAL3 ;
        RECT 274.04 0.0 275.44 2.8 ;
    END
  END s_gnd
  PIN n_vinj
    DIRECTION INOUT ;
    USE SIGNAL ;
    PORT
      LAYER METAL3 ;
        RECT 260.04 141.6 261.44 144.4 ;
    END
  END n_vinj
  PIN s_vinj
    DIRECTION INOUT ;
    USE SIGNAL ;
    PORT
      LAYER METAL3 ;
        RECT 260.04 0.0 261.44 2.8 ;
    END
  END s_vinj
  PIN n_avdd
    DIRECTION INOUT ;
    USE SIGNAL ;
    PORT
      LAYER METAL3 ;
        RECT 246.04 141.6 247.44 144.4 ;
    END
  END n_avdd
  PIN s_avdd
    DIRECTION INOUT ;
    USE SIGNAL ;
    PORT
      LAYER METAL3 ;
        RECT 246.04 0.0 247.44 2.8 ;
    END
  END s_avdd
  PIN s_Code<7>
    DIRECTION INOUT ;
    USE SIGNAL ;
    PORT
      LAYER METAL3 ;
        RECT 139.3 0.0 140.7 2.8 ;
    END
  END s_Code<7>
  PIN s_Code<6>
    DIRECTION INOUT ;
    USE SIGNAL ;
    PORT
      LAYER METAL3 ;
        RECT 125.3 0.0 126.7 2.8 ;
    END
  END s_Code<6>
  PIN s_Code<5>
    DIRECTION INOUT ;
    USE SIGNAL ;
    PORT
      LAYER METAL3 ;
        RECT 111.3 0.0 112.7 2.8 ;
    END
  END s_Code<5>
  PIN s_Code<4>
    DIRECTION INOUT ;
    USE SIGNAL ;
    PORT
      LAYER METAL3 ;
        RECT 97.3 0.0 98.7 2.8 ;
    END
  END s_Code<4>
  PIN n_GateEnable
    DIRECTION INOUT ;
    USE SIGNAL ;
    PORT
      LAYER METAL3 ;
        RECT 83.3 141.6 84.7 144.4 ;
    END
  END n_GateEnable
  PIN s_Code<3>
    DIRECTION INOUT ;
    USE SIGNAL ;
    PORT
      LAYER METAL3 ;
        RECT 83.3 0.0 84.7 2.8 ;
    END
  END s_Code<3>
  PIN s_Code<2>
    DIRECTION INOUT ;
    USE SIGNAL ;
    PORT
      LAYER METAL3 ;
        RECT 69.3 0.0 70.7 2.8 ;
    END
  END s_Code<2>
  PIN n_VTUN
    DIRECTION INOUT ;
    USE SIGNAL ;
    PORT
      LAYER METAL3 ;
        RECT 69.3 141.6 70.7 144.4 ;
    END
  END n_VTUN
  PIN s_Code<1>
    DIRECTION INOUT ;
    USE SIGNAL ;
    PORT
      LAYER METAL3 ;
        RECT 55.3 0.0 56.7 2.8 ;
    END
  END s_Code<1>
  PIN n_VGPROG
    DIRECTION INOUT ;
    USE SIGNAL ;
    PORT
      LAYER METAL3 ;
        RECT 55.3 141.6 56.7 144.4 ;
    END
  END n_VGPROG
  PIN s_Code<0>
    DIRECTION INOUT ;
    USE SIGNAL ;
    PORT
      LAYER METAL3 ;
        RECT 41.3 0.0 42.7 2.8 ;
    END
  END s_Code<0>
  PIN n_VGRUN
    DIRECTION INOUT ;
    USE SIGNAL ;
    PORT
      LAYER METAL3 ;
        RECT 41.3 141.6 42.7 144.4 ;
    END
  END n_VGRUN
  PIN s_Prog_Drainline
    DIRECTION INOUT ;
    USE SIGNAL ;
    PORT
      LAYER METAL3 ;
        RECT 27.3 0.0 28.7 2.8 ;
    END
  END s_Prog_Drainline
  PIN n_Run
    DIRECTION INOUT ;
    USE SIGNAL ;
    PORT
      LAYER METAL3 ;
        RECT 27.3 141.6 28.7 144.4 ;
    END
  END n_Run
  PIN s_Run_Drainline
    DIRECTION INOUT ;
    USE SIGNAL ;
    PORT
      LAYER METAL3 ;
        RECT 13.3 0.0 14.7 2.8 ;
    END
  END s_Run_Drainline
  PIN n_Prog
    DIRECTION INOUT ;
    USE SIGNAL ;
    PORT
      LAYER METAL3 ;
        RECT 13.3 141.6 14.7 144.4 ;
    END
  END n_Prog
  PIN w_DrainEnable
    DIRECTION INOUT ;
    USE SIGNAL ;
    PORT
      LAYER METAL3 ;
        RECT 0.0 101.0 2.8 102.4 ;
    END
  END w_DrainEnable
  PIN w_DrainB<0>
    DIRECTION INOUT ;
    USE SIGNAL ;
    PORT
      LAYER METAL3 ;
        RECT 0.0 129.0 2.8 130.4 ;
    END
  END w_DrainB<0>
  PIN w_DrainB<1>
    DIRECTION INOUT ;
    USE SIGNAL ;
    PORT
      LAYER METAL3 ;
        RECT 0.0 115.0 2.8 116.4 ;
    END
  END w_DrainB<1>
  PIN w_GateB<0>
    DIRECTION INOUT ;
    USE SIGNAL ;
    PORT
      LAYER METAL3 ;
        RECT 0.0 87.0 2.8 88.4 ;
    END
  END w_GateB<0>
  PIN w_GateB<1>
    DIRECTION INOUT ;
    USE SIGNAL ;
    PORT
      LAYER METAL3 ;
        RECT 0.0 73.0 2.8 74.4 ;
    END
  END w_GateB<1>
  PIN w_CLK
    DIRECTION INOUT ;
    USE SIGNAL ;
    PORT
      LAYER METAL3 ;
        RECT 0.0 59.0 2.8 60.4 ;
    END
  END w_CLK
  PIN w_RST
    DIRECTION INOUT ;
    USE SIGNAL ;
    PORT
      LAYER METAL3 ;
        RECT 0.0 45.0 2.8 46.4 ;
    END
  END w_RST
  PIN w_Vin
    DIRECTION INOUT ;
    USE SIGNAL ;
    PORT
      LAYER METAL3 ;
        RECT 0.0 31.0 2.8 32.4 ;
    END
  END w_Vin
END RampADC_synth

MACRO AlgorithmicADC_synth
  PIN n_vinj
    DIRECTION INOUT ;
    USE SIGNAL ;
    PORT
      LAYER METAL3 ;
        RECT 208.91 217.6 210.31 220.4 ;
    END
  END n_vinj
  PIN n_RUN
    DIRECTION INOUT ;
    USE SIGNAL ;
    PORT
      LAYER METAL3 ;
        RECT 27.3 217.6 28.7 220.4 ;
    END
  END n_RUN
  PIN n_avdd
    DIRECTION INOUT ;
    USE SIGNAL ;
    PORT
      LAYER METAL3 ;
        RECT 194.91 217.6 196.31 220.4 ;
    END
  END n_avdd
  PIN n_VTUN
    DIRECTION INOUT ;
    USE SIGNAL ;
    PORT
      LAYER METAL3 ;
        RECT 69.3 217.6 70.7 220.4 ;
    END
  END n_VTUN
  PIN n_PROG
    DIRECTION INOUT ;
    USE SIGNAL ;
    PORT
      LAYER METAL3 ;
        RECT 13.3 217.6 14.7 220.4 ;
    END
  END n_PROG
  PIN n_VGRUN
    DIRECTION INOUT ;
    USE SIGNAL ;
    PORT
      LAYER METAL3 ;
        RECT 41.3 217.6 42.7 220.4 ;
    END
  END n_VGRUN
  PIN n_VGPROG
    DIRECTION INOUT ;
    USE SIGNAL ;
    PORT
      LAYER METAL3 ;
        RECT 55.3 217.6 56.7 220.4 ;
    END
  END n_VGPROG
  PIN n_GateEnable
    DIRECTION INOUT ;
    USE SIGNAL ;
    PORT
      LAYER METAL3 ;
        RECT 83.3 217.6 84.7 220.4 ;
    END
  END n_GateEnable
  PIN n_gnd
    DIRECTION INOUT ;
    USE SIGNAL ;
    PORT
      LAYER METAL3 ;
        RECT 222.91 217.6 224.31 220.4 ;
    END
  END n_gnd
  PIN w_DrainB<0>
    DIRECTION INOUT ;
    USE SIGNAL ;
    PORT
      LAYER METAL3 ;
        RECT 0.0 205.0 2.8 206.4 ;
    END
  END w_DrainB<0>
  PIN e_CLK_Sample
    DIRECTION INOUT ;
    USE SIGNAL ;
    PORT
      LAYER METAL3 ;
        RECT 249.51 205.0 252.31 206.4 ;
    END
  END e_CLK_Sample
  PIN w_DrainB<1>
    DIRECTION INOUT ;
    USE SIGNAL ;
    PORT
      LAYER METAL3 ;
        RECT 0.0 191.0 2.8 192.4 ;
    END
  END w_DrainB<1>
  PIN e_CLK_Amp
    DIRECTION INOUT ;
    USE SIGNAL ;
    PORT
      LAYER METAL3 ;
        RECT 249.51 191.0 252.31 192.4 ;
    END
  END e_CLK_Amp
  PIN w_DrainB<2>
    DIRECTION INOUT ;
    USE SIGNAL ;
    PORT
      LAYER METAL3 ;
        RECT 0.0 177.0 2.8 178.4 ;
    END
  END w_DrainB<2>
  PIN e_CLK_Load
    DIRECTION INOUT ;
    USE SIGNAL ;
    PORT
      LAYER METAL3 ;
        RECT 249.51 177.0 252.31 178.4 ;
    END
  END e_CLK_Load
  PIN w_DrainB<3>
    DIRECTION INOUT ;
    USE SIGNAL ;
    PORT
      LAYER METAL3 ;
        RECT 0.0 163.0 2.8 164.4 ;
    END
  END w_DrainB<3>
  PIN w_DrainEnable
    DIRECTION INOUT ;
    USE SIGNAL ;
    PORT
      LAYER METAL3 ;
        RECT 0.0 149.0 2.8 150.4 ;
    END
  END w_DrainEnable
  PIN w_GateB<0>
    DIRECTION INOUT ;
    USE SIGNAL ;
    PORT
      LAYER METAL3 ;
        RECT 0.0 135.0 2.8 136.4 ;
    END
  END w_GateB<0>
  PIN w_GateB<1>
    DIRECTION INOUT ;
    USE SIGNAL ;
    PORT
      LAYER METAL3 ;
        RECT 0.0 121.0 2.8 122.4 ;
    END
  END w_GateB<1>
  PIN w_VIN
    DIRECTION INOUT ;
    USE SIGNAL ;
    PORT
      LAYER METAL3 ;
        RECT 0.0 107.0 2.8 108.4 ;
    END
  END w_VIN
  PIN s_Drainline_Run
    DIRECTION INOUT ;
    USE SIGNAL ;
    PORT
      LAYER METAL3 ;
        RECT 27.3 0.0 28.7 2.8 ;
    END
  END s_Drainline_Run
  PIN s_vinj
    DIRECTION INOUT ;
    USE SIGNAL ;
    PORT
      LAYER METAL3 ;
        RECT 208.91 0.0 210.31 2.8 ;
    END
  END s_vinj
  PIN s_Drainline_Prog
    DIRECTION INOUT ;
    USE SIGNAL ;
    PORT
      LAYER METAL3 ;
        RECT 13.3 0.0 14.7 2.8 ;
    END
  END s_Drainline_Prog
  PIN s_avdd
    DIRECTION INOUT ;
    USE SIGNAL ;
    PORT
      LAYER METAL3 ;
        RECT 194.91 0.0 196.31 2.8 ;
    END
  END s_avdd
  PIN s_VRES
    DIRECTION INOUT ;
    USE SIGNAL ;
    PORT
      LAYER METAL3 ;
        RECT 55.3 0.0 56.7 2.8 ;
    END
  END s_VRES
  PIN s_CLK_RST
    DIRECTION INOUT ;
    USE SIGNAL ;
    PORT
      LAYER METAL3 ;
        RECT 41.3 0.0 42.7 2.8 ;
    END
  END s_CLK_RST
  PIN s_gnd
    DIRECTION INOUT ;
    USE SIGNAL ;
    PORT
      LAYER METAL3 ;
        RECT 222.91 0.0 224.31 2.8 ;
    END
  END s_gnd
END AlgorithmicADC_synth

MACRO AveragerDAC_synth
  PIN w_GateB<0>
    DIRECTION INOUT ;
    USE SIGNAL ;
    PORT
      LAYER METAL3 ;
        RECT 0.0 168.0 2.8 169.4 ;
    END
  END w_GateB<0>
  PIN n_vinj
    DIRECTION INOUT ;
    USE SIGNAL ;
    PORT
      LAYER METAL3 ;
        RECT 161.03 250.6 162.43 253.4 ;
    END
  END n_vinj
  PIN n_gnd
    DIRECTION INOUT ;
    USE SIGNAL ;
    PORT
      LAYER METAL3 ;
        RECT 175.03 250.6 176.43 253.4 ;
    END
  END n_gnd
  PIN n_VGRUN
    DIRECTION INOUT ;
    USE SIGNAL ;
    PORT
      LAYER METAL3 ;
        RECT 41.3 250.6 42.7 253.4 ;
    END
  END n_VGRUN
  PIN w_DrainEnable
    DIRECTION INOUT ;
    USE SIGNAL ;
    PORT
      LAYER METAL3 ;
        RECT 0.0 182.0 2.8 183.4 ;
    END
  END w_DrainEnable
  PIN w_GateB<1>
    DIRECTION INOUT ;
    USE SIGNAL ;
    PORT
      LAYER METAL3 ;
        RECT 0.0 154.0 2.8 155.4 ;
    END
  END w_GateB<1>
  PIN e_Code<3>
    DIRECTION INOUT ;
    USE SIGNAL ;
    PORT
      LAYER METAL3 ;
        RECT 215.63 196.0 218.43 197.4 ;
    END
  END e_Code<3>
  PIN n_VGPROG
    DIRECTION INOUT ;
    USE SIGNAL ;
    PORT
      LAYER METAL3 ;
        RECT 55.3 250.6 56.7 253.4 ;
    END
  END n_VGPROG
  PIN e_Code<4>
    DIRECTION INOUT ;
    USE SIGNAL ;
    PORT
      LAYER METAL3 ;
        RECT 215.63 182.0 218.43 183.4 ;
    END
  END e_Code<4>
  PIN w_DrainB<3>
    DIRECTION INOUT ;
    USE SIGNAL ;
    PORT
      LAYER METAL3 ;
        RECT 0.0 196.0 2.8 197.4 ;
    END
  END w_DrainB<3>
  PIN e_Code<2>
    DIRECTION INOUT ;
    USE SIGNAL ;
    PORT
      LAYER METAL3 ;
        RECT 215.63 210.0 218.43 211.4 ;
    END
  END e_Code<2>
  PIN e_Code<1>
    DIRECTION INOUT ;
    USE SIGNAL ;
    PORT
      LAYER METAL3 ;
        RECT 215.63 224.0 218.43 225.4 ;
    END
  END e_Code<1>
  PIN e_Code<0>
    DIRECTION INOUT ;
    USE SIGNAL ;
    PORT
      LAYER METAL3 ;
        RECT 215.63 238.0 218.43 239.4 ;
    END
  END e_Code<0>
  PIN w_DrainB<1>
    DIRECTION INOUT ;
    USE SIGNAL ;
    PORT
      LAYER METAL3 ;
        RECT 0.0 224.0 2.8 225.4 ;
    END
  END w_DrainB<1>
  PIN n_Prog
    DIRECTION INOUT ;
    USE SIGNAL ;
    PORT
      LAYER METAL3 ;
        RECT 13.3 250.6 14.7 253.4 ;
    END
  END n_Prog
  PIN n_GateEnable
    DIRECTION INOUT ;
    USE SIGNAL ;
    PORT
      LAYER METAL3 ;
        RECT 83.3 250.6 84.7 253.4 ;
    END
  END n_GateEnable
  PIN n_Run
    DIRECTION INOUT ;
    USE SIGNAL ;
    PORT
      LAYER METAL3 ;
        RECT 27.3 250.6 28.7 253.4 ;
    END
  END n_Run
  PIN s_gnd
    DIRECTION INOUT ;
    USE SIGNAL ;
    PORT
      LAYER METAL3 ;
        RECT 175.03 0.0 176.43 2.8 ;
    END
  END s_gnd
  PIN s_Vout
    DIRECTION INOUT ;
    USE SIGNAL ;
    PORT
      LAYER METAL3 ;
        RECT 41.3 0.0 42.7 2.8 ;
    END
  END s_Vout
  PIN w_DrainB<2>
    DIRECTION INOUT ;
    USE SIGNAL ;
    PORT
      LAYER METAL3 ;
        RECT 0.0 210.0 2.8 211.4 ;
    END
  END w_DrainB<2>
  PIN w_DrainB<0>
    DIRECTION INOUT ;
    USE SIGNAL ;
    PORT
      LAYER METAL3 ;
        RECT 0.0 238.0 2.8 239.4 ;
    END
  END w_DrainB<0>
  PIN n_VTUN
    DIRECTION INOUT ;
    USE SIGNAL ;
    PORT
      LAYER METAL3 ;
        RECT 69.3 250.6 70.7 253.4 ;
    END
  END n_VTUN
  PIN n_avdd
    DIRECTION INOUT ;
    USE SIGNAL ;
    PORT
      LAYER METAL3 ;
        RECT 189.03 250.6 190.43 253.4 ;
    END
  END n_avdd
  PIN s_avdd
    DIRECTION INOUT ;
    USE SIGNAL ;
    PORT
      LAYER METAL3 ;
        RECT 189.03 0.0 190.43 2.8 ;
    END
  END s_avdd
  PIN s_Prog_Drainline
    DIRECTION INOUT ;
    USE SIGNAL ;
    PORT
      LAYER METAL3 ;
        RECT 27.3 0.0 28.7 2.8 ;
    END
  END s_Prog_Drainline
  PIN s_vinj
    DIRECTION INOUT ;
    USE SIGNAL ;
    PORT
      LAYER METAL3 ;
        RECT 161.03 0.0 162.43 2.8 ;
    END
  END s_vinj
  PIN s_Run_Drainline
    DIRECTION INOUT ;
    USE SIGNAL ;
    PORT
      LAYER METAL3 ;
        RECT 13.3 0.0 14.7 2.8 ;
    END
  END s_Run_Drainline
END AveragerDAC_synth

MACRO frame_6p9mm_2mm_edit
  PIN gnd_E<1>
    DIRECTION INOUT ;
    USE SIGNAL ;
    PORT
      LAYER METAL2 ;
        RECT 6705.1 1243.55 6705.9 1251.35 ;
    END
  END gnd_E<1>
  PIN gnd_E<0>
    DIRECTION INOUT ;
    USE SIGNAL ;
    PORT
      LAYER METAL2 ;
        RECT 6705.1 1561.55 6705.9 1569.35 ;
    END
  END gnd_E<0>
  PIN gnd_S<2>
    DIRECTION INOUT ;
    USE SIGNAL ;
    PORT
      LAYER METAL2 ;
        RECT 6202.1 217.55 6209.9 218.35 ;
    END
  END gnd_S<2>
  PIN esd_vdd_S<2>
    DIRECTION INOUT ;
    USE SIGNAL ;
    PORT
      LAYER METAL2 ;
        RECT 6308.1 217.56 6315.9 218.35 ;
    END
  END esd_vdd_S<2>
  PIN avdd_S<2>
    DIRECTION INOUT ;
    USE SIGNAL ;
    PORT
      LAYER METAL2 ;
        RECT 6414.1 217.55 6421.9 218.35 ;
    END
  END avdd_S<2>
  PIN VINJ_S<2>
    DIRECTION INOUT ;
    USE SIGNAL ;
    PORT
      LAYER METAL2 ;
        RECT 6520.1 217.55 6527.9 218.35 ;
    END
  END VINJ_S<2>
  PIN esd_vdd_S<1>
    DIRECTION INOUT ;
    USE SIGNAL ;
    PORT
      LAYER METAL2 ;
        RECT 3340.1 217.56 3347.9 218.35 ;
    END
  END esd_vdd_S<1>
  PIN avdd_S<1>
    DIRECTION INOUT ;
    USE SIGNAL ;
    PORT
      LAYER METAL2 ;
        RECT 3446.1 217.55 3453.9 218.35 ;
    END
  END avdd_S<1>
  PIN VINJ_S<1>
    DIRECTION INOUT ;
    USE SIGNAL ;
    PORT
      LAYER METAL2 ;
        RECT 3552.1 217.55 3559.9 218.35 ;
    END
  END VINJ_S<1>
  PIN gnd_S<1>
    DIRECTION INOUT ;
    USE SIGNAL ;
    PORT
      LAYER METAL2 ;
        RECT 3234.1 217.55 3241.9 218.35 ;
    END
  END gnd_S<1>
  PIN VINJ_S<0>
    DIRECTION INOUT ;
    USE SIGNAL ;
    PORT
      LAYER METAL2 ;
        RECT 584.1 217.55 591.9 218.35 ;
    END
  END VINJ_S<0>
  PIN avdd_S<0>
    DIRECTION INOUT ;
    USE SIGNAL ;
    PORT
      LAYER METAL2 ;
        RECT 478.1 217.55 485.9 218.35 ;
    END
  END avdd_S<0>
  PIN esd_vdd_S<0>
    DIRECTION INOUT ;
    USE SIGNAL ;
    PORT
      LAYER METAL2 ;
        RECT 372.1 217.56 379.9 218.35 ;
    END
  END esd_vdd_S<0>
  PIN gnd_S<0>
    DIRECTION INOUT ;
    USE SIGNAL ;
    PORT
      LAYER METAL2 ;
        RECT 266.1 217.55 273.9 218.35 ;
    END
  END gnd_S<0>
  PIN VINJ_N<2>
    DIRECTION INOUT ;
    USE SIGNAL ;
    PORT
      LAYER METAL2 ;
        RECT 6520.1 1852.55 6527.9 1853.35 ;
    END
  END VINJ_N<2>
  PIN avdd_N<2>
    DIRECTION INOUT ;
    USE SIGNAL ;
    PORT
      LAYER METAL2 ;
        RECT 6414.1 1852.55 6421.9 1853.35 ;
    END
  END avdd_N<2>
  PIN esd_vdd_N<2>
    DIRECTION INOUT ;
    USE SIGNAL ;
    PORT
      LAYER METAL2 ;
        RECT 6308.1 1852.55 6315.9 1853.35 ;
    END
  END esd_vdd_N<2>
  PIN gnd_N<8>
    DIRECTION INOUT ;
    USE SIGNAL ;
    PORT
      LAYER METAL2 ;
        RECT 6202.1 1852.55 6209.9 1853.35 ;
    END
  END gnd_N<8>
  PIN gnd_N<7>
    DIRECTION INOUT ;
    USE SIGNAL ;
    PORT
      LAYER METAL2 ;
        RECT 5990.1 1852.55 5997.9 1853.35 ;
    END
  END gnd_N<7>
  PIN gnd_N<6>
    DIRECTION INOUT ;
    USE SIGNAL ;
    PORT
      LAYER METAL2 ;
        RECT 3976.1 1852.55 3983.9 1853.35 ;
    END
  END gnd_N<6>
  PIN gnd_N<5>
    DIRECTION INOUT ;
    USE SIGNAL ;
    PORT
      LAYER METAL2 ;
        RECT 3764.1 1852.55 3771.9 1853.35 ;
    END
  END gnd_N<5>
  PIN VINJ_N<1>
    DIRECTION INOUT ;
    USE SIGNAL ;
    PORT
      LAYER METAL2 ;
        RECT 3552.1 1852.55 3559.9 1853.35 ;
    END
  END VINJ_N<1>
  PIN avdd_N<1>
    DIRECTION INOUT ;
    USE SIGNAL ;
    PORT
      LAYER METAL2 ;
        RECT 3446.1 1852.55 3453.9 1853.35 ;
    END
  END avdd_N<1>
  PIN esd_vdd_N<1>
    DIRECTION INOUT ;
    USE SIGNAL ;
    PORT
      LAYER METAL2 ;
        RECT 3340.1 1852.55 3347.9 1853.35 ;
    END
  END esd_vdd_N<1>
  PIN gnd_N<4>
    DIRECTION INOUT ;
    USE SIGNAL ;
    PORT
      LAYER METAL2 ;
        RECT 3234.1 1852.55 3241.9 1853.35 ;
    END
  END gnd_N<4>
  PIN gnd_N<3>
    DIRECTION INOUT ;
    USE SIGNAL ;
    PORT
      LAYER METAL2 ;
        RECT 3022.1 1852.55 3029.9 1853.35 ;
    END
  END gnd_N<3>
  PIN gnd_N<2>
    DIRECTION INOUT ;
    USE SIGNAL ;
    PORT
      LAYER METAL2 ;
        RECT 1008.1 1852.55 1015.9 1853.35 ;
    END
  END gnd_N<2>
  PIN gnd_N<1>
    DIRECTION INOUT ;
    USE SIGNAL ;
    PORT
      LAYER METAL2 ;
        RECT 796.1 1852.55 803.9 1853.35 ;
    END
  END gnd_N<1>
  PIN VINJ_N<0>
    DIRECTION INOUT ;
    USE SIGNAL ;
    PORT
      LAYER METAL2 ;
        RECT 584.1 1852.55 591.9 1853.35 ;
    END
  END VINJ_N<0>
  PIN avdd_N<0>
    DIRECTION INOUT ;
    USE SIGNAL ;
    PORT
      LAYER METAL2 ;
        RECT 478.1 1852.55 485.9 1853.35 ;
    END
  END avdd_N<0>
  PIN esd_vdd_N<0>
    DIRECTION INOUT ;
    USE SIGNAL ;
    PORT
      LAYER METAL2 ;
        RECT 372.1 1852.56 379.9 1853.35 ;
    END
  END esd_vdd_N<0>
  PIN gnd_N<0>
    DIRECTION INOUT ;
    USE SIGNAL ;
    PORT
      LAYER METAL2 ;
        RECT 266.11 1852.55 273.9 1853.35 ;
    END
  END gnd_N<0>
  PIN gnd_W<1>
    DIRECTION INOUT ;
    USE SIGNAL ;
    PORT
      LAYER METAL2 ;
        RECT 194.1 1243.55 194.9 1251.35 ;
    END
  END gnd_W<1>
  PIN gnd_W<0>
    DIRECTION INOUT ;
    USE SIGNAL ;
    PORT
      LAYER METAL2 ;
        RECT 194.1 1561.55 194.9 1569.35 ;
    END
  END gnd_W<0>
  PIN IO_E<8>
    DIRECTION INOUT ;
    USE SIGNAL ;
    PORT
      LAYER METAL2 ;
        RECT 6705.1 289.55 6705.9 297.35 ;
    END
  END IO_E<8>
  PIN IO_E<7>
    DIRECTION INOUT ;
    USE SIGNAL ;
    PORT
      LAYER METAL2 ;
        RECT 6705.1 395.55 6705.9 403.35 ;
    END
  END IO_E<7>
  PIN IO_E<6>
    DIRECTION INOUT ;
    USE SIGNAL ;
    PORT
      LAYER METAL2 ;
        RECT 6705.1 501.55 6705.9 509.35 ;
    END
  END IO_E<6>
  PIN IO_E<5>
    DIRECTION INOUT ;
    USE SIGNAL ;
    PORT
      LAYER METAL2 ;
        RECT 6705.1 607.55 6705.9 615.35 ;
    END
  END IO_E<5>
  PIN IO_E<4>
    DIRECTION INOUT ;
    USE SIGNAL ;
    PORT
      LAYER METAL2 ;
        RECT 6705.1 713.55 6705.9 721.35 ;
    END
  END IO_E<4>
  PIN IO_E<3>
    DIRECTION INOUT ;
    USE SIGNAL ;
    PORT
      LAYER METAL2 ;
        RECT 6705.1 819.55 6705.9 827.35 ;
    END
  END IO_E<3>
  PIN IO_E<2>
    DIRECTION INOUT ;
    USE SIGNAL ;
    PORT
      LAYER METAL2 ;
        RECT 6705.1 925.55 6705.9 933.35 ;
    END
  END IO_E<2>
  PIN IO_E<1>
    DIRECTION INOUT ;
    USE SIGNAL ;
    PORT
      LAYER METAL2 ;
        RECT 6705.1 1031.55 6705.9 1039.35 ;
    END
  END IO_E<1>
  PIN IO_E<0>
    DIRECTION INOUT ;
    USE SIGNAL ;
    PORT
      LAYER METAL2 ;
        RECT 6705.1 1137.55 6705.9 1145.35 ;
    END
  END IO_E<0>
  PIN IO_E_RES<1>
    DIRECTION INOUT ;
    USE SIGNAL ;
    PORT
      LAYER METAL2 ;
        RECT 6704.52 1349.55 6705.32 1357.35 ;
    END
  END IO_E_RES<1>
  PIN IO_E_RES<0>
    DIRECTION INOUT ;
    USE SIGNAL ;
    PORT
      LAYER METAL2 ;
        RECT 6704.52 1455.55 6705.32 1463.35 ;
    END
  END IO_E_RES<0>
  PIN IO_Bare_E<1>
    DIRECTION INOUT ;
    USE SIGNAL ;
    PORT
      LAYER METAL2 ;
        RECT 6704.52 1667.55 6705.32 1675.35 ;
    END
  END IO_Bare_E<1>
  PIN IO_Bare_E<0>
    DIRECTION INOUT ;
    USE SIGNAL ;
    PORT
      LAYER METAL2 ;
        RECT 6704.52 1773.55 6705.32 1781.35 ;
    END
  END IO_Bare_E<0>
  PIN IO_W<8>
    DIRECTION INOUT ;
    USE SIGNAL ;
    PORT
      LAYER METAL2 ;
        RECT 194.1 289.55 194.9 297.35 ;
    END
  END IO_W<8>
  PIN IO_W<7>
    DIRECTION INOUT ;
    USE SIGNAL ;
    PORT
      LAYER METAL2 ;
        RECT 194.1 395.55 194.9 403.35 ;
    END
  END IO_W<7>
  PIN IO_W<6>
    DIRECTION INOUT ;
    USE SIGNAL ;
    PORT
      LAYER METAL2 ;
        RECT 194.1 501.55 194.9 509.35 ;
    END
  END IO_W<6>
  PIN IO_W<5>
    DIRECTION INOUT ;
    USE SIGNAL ;
    PORT
      LAYER METAL2 ;
        RECT 194.1 607.55 194.9 615.35 ;
    END
  END IO_W<5>
  PIN IO_W<4>
    DIRECTION INOUT ;
    USE SIGNAL ;
    PORT
      LAYER METAL2 ;
        RECT 194.1 713.55 194.9 721.35 ;
    END
  END IO_W<4>
  PIN IO_W<3>
    DIRECTION INOUT ;
    USE SIGNAL ;
    PORT
      LAYER METAL2 ;
        RECT 194.1 819.55 194.9 827.35 ;
    END
  END IO_W<3>
  PIN IO_W<2>
    DIRECTION INOUT ;
    USE SIGNAL ;
    PORT
      LAYER METAL2 ;
        RECT 194.1 925.55 194.9 933.35 ;
    END
  END IO_W<2>
  PIN IO_W<1>
    DIRECTION INOUT ;
    USE SIGNAL ;
    PORT
      LAYER METAL2 ;
        RECT 194.1 1031.55 194.9 1039.35 ;
    END
  END IO_W<1>
  PIN IO_W<0>
    DIRECTION INOUT ;
    USE SIGNAL ;
    PORT
      LAYER METAL2 ;
        RECT 194.1 1137.55 194.9 1145.35 ;
    END
  END IO_W<0>
  PIN IO_W_RES<1>
    DIRECTION INOUT ;
    USE SIGNAL ;
    PORT
      LAYER METAL2 ;
        RECT 194.68 1349.55 195.48 1357.35 ;
    END
  END IO_W_RES<1>
  PIN IO_W_RES<0>
    DIRECTION INOUT ;
    USE SIGNAL ;
    PORT
      LAYER METAL2 ;
        RECT 194.68 1455.55 195.48 1463.35 ;
    END
  END IO_W_RES<0>
  PIN IO_Bare_W<1>
    DIRECTION INOUT ;
    USE SIGNAL ;
    PORT
      LAYER METAL2 ;
        RECT 194.68 1667.55 195.48 1675.35 ;
    END
  END IO_Bare_W<1>
  PIN IO_Bare_W<0>
    DIRECTION INOUT ;
    USE SIGNAL ;
    PORT
      LAYER METAL2 ;
        RECT 194.68 1773.55 195.48 1781.35 ;
    END
  END IO_Bare_W<0>
  PIN DVDD_S<2>
    DIRECTION INOUT ;
    USE SIGNAL ;
    PORT
      LAYER METAL2 ;
        RECT 6626.1 217.55 6633.9 218.35 ;
    END
  END DVDD_S<2>
  PIN IO_S<45>
    DIRECTION INOUT ;
    USE SIGNAL ;
    PORT
      LAYER METAL2 ;
        RECT 6096.1 217.55 6103.9 218.35 ;
    END
  END IO_S<45>
  PIN IO_S<44>
    DIRECTION INOUT ;
    USE SIGNAL ;
    PORT
      LAYER METAL2 ;
        RECT 5990.1 217.55 5997.9 218.35 ;
    END
  END IO_S<44>
  PIN IO_S<43>
    DIRECTION INOUT ;
    USE SIGNAL ;
    PORT
      LAYER METAL2 ;
        RECT 5884.1 217.55 5891.9 218.35 ;
    END
  END IO_S<43>
  PIN IO_S<42>
    DIRECTION INOUT ;
    USE SIGNAL ;
    PORT
      LAYER METAL2 ;
        RECT 5778.1 217.55 5785.9 218.35 ;
    END
  END IO_S<42>
  PIN IO_S<41>
    DIRECTION INOUT ;
    USE SIGNAL ;
    PORT
      LAYER METAL2 ;
        RECT 5672.1 217.55 5679.9 218.35 ;
    END
  END IO_S<41>
  PIN IO_S<40>
    DIRECTION INOUT ;
    USE SIGNAL ;
    PORT
      LAYER METAL2 ;
        RECT 5566.1 217.55 5573.9 218.35 ;
    END
  END IO_S<40>
  PIN IO_S<39>
    DIRECTION INOUT ;
    USE SIGNAL ;
    PORT
      LAYER METAL2 ;
        RECT 5460.1 217.55 5467.9 218.35 ;
    END
  END IO_S<39>
  PIN IO_S<38>
    DIRECTION INOUT ;
    USE SIGNAL ;
    PORT
      LAYER METAL2 ;
        RECT 5354.1 217.55 5361.9 218.35 ;
    END
  END IO_S<38>
  PIN IO_S<37>
    DIRECTION INOUT ;
    USE SIGNAL ;
    PORT
      LAYER METAL2 ;
        RECT 5248.1 217.55 5255.9 218.35 ;
    END
  END IO_S<37>
  PIN IO_S<36>
    DIRECTION INOUT ;
    USE SIGNAL ;
    PORT
      LAYER METAL2 ;
        RECT 5142.1 217.55 5149.9 218.35 ;
    END
  END IO_S<36>
  PIN IO_S<35>
    DIRECTION INOUT ;
    USE SIGNAL ;
    PORT
      LAYER METAL2 ;
        RECT 5036.1 217.55 5043.9 218.35 ;
    END
  END IO_S<35>
  PIN IO_S<34>
    DIRECTION INOUT ;
    USE SIGNAL ;
    PORT
      LAYER METAL2 ;
        RECT 4930.1 217.55 4937.9 218.35 ;
    END
  END IO_S<34>
  PIN IO_S<33>
    DIRECTION INOUT ;
    USE SIGNAL ;
    PORT
      LAYER METAL2 ;
        RECT 4824.1 217.55 4831.9 218.35 ;
    END
  END IO_S<33>
  PIN IO_S<32>
    DIRECTION INOUT ;
    USE SIGNAL ;
    PORT
      LAYER METAL2 ;
        RECT 4718.1 217.55 4725.9 218.35 ;
    END
  END IO_S<32>
  PIN IO_S<31>
    DIRECTION INOUT ;
    USE SIGNAL ;
    PORT
      LAYER METAL2 ;
        RECT 4612.1 217.55 4619.9 218.35 ;
    END
  END IO_S<31>
  PIN IO_S<30>
    DIRECTION INOUT ;
    USE SIGNAL ;
    PORT
      LAYER METAL2 ;
        RECT 4506.1 217.55 4513.9 218.35 ;
    END
  END IO_S<30>
  PIN IO_S<29>
    DIRECTION INOUT ;
    USE SIGNAL ;
    PORT
      LAYER METAL2 ;
        RECT 4400.1 217.55 4407.9 218.35 ;
    END
  END IO_S<29>
  PIN IO_S<28>
    DIRECTION INOUT ;
    USE SIGNAL ;
    PORT
      LAYER METAL2 ;
        RECT 4294.1 217.55 4301.9 218.35 ;
    END
  END IO_S<28>
  PIN IO_S<27>
    DIRECTION INOUT ;
    USE SIGNAL ;
    PORT
      LAYER METAL2 ;
        RECT 4188.1 217.55 4195.9 218.35 ;
    END
  END IO_S<27>
  PIN IO_S<26>
    DIRECTION INOUT ;
    USE SIGNAL ;
    PORT
      LAYER METAL2 ;
        RECT 4082.1 217.55 4089.9 218.35 ;
    END
  END IO_S<26>
  PIN IO_S<25>
    DIRECTION INOUT ;
    USE SIGNAL ;
    PORT
      LAYER METAL2 ;
        RECT 3976.1 217.55 3983.9 218.35 ;
    END
  END IO_S<25>
  PIN IO_S<24>
    DIRECTION INOUT ;
    USE SIGNAL ;
    PORT
      LAYER METAL2 ;
        RECT 3870.1 217.55 3877.9 218.35 ;
    END
  END IO_S<24>
  PIN IO_S<23>
    DIRECTION INOUT ;
    USE SIGNAL ;
    PORT
      LAYER METAL2 ;
        RECT 3764.1 217.55 3771.9 218.35 ;
    END
  END IO_S<23>
  PIN DVDD_S<1>
    DIRECTION INOUT ;
    USE SIGNAL ;
    PORT
      LAYER METAL2 ;
        RECT 3658.1 217.55 3665.9 218.35 ;
    END
  END DVDD_S<1>
  PIN IO_S<22>
    DIRECTION INOUT ;
    USE SIGNAL ;
    PORT
      LAYER METAL2 ;
        RECT 3128.1 217.55 3135.9 218.35 ;
    END
  END IO_S<22>
  PIN IO_S<21>
    DIRECTION INOUT ;
    USE SIGNAL ;
    PORT
      LAYER METAL2 ;
        RECT 3022.1 217.55 3029.9 218.35 ;
    END
  END IO_S<21>
  PIN IO_S<20>
    DIRECTION INOUT ;
    USE SIGNAL ;
    PORT
      LAYER METAL2 ;
        RECT 2916.1 217.55 2923.9 218.35 ;
    END
  END IO_S<20>
  PIN IO_S<19>
    DIRECTION INOUT ;
    USE SIGNAL ;
    PORT
      LAYER METAL2 ;
        RECT 2810.1 217.55 2817.9 218.35 ;
    END
  END IO_S<19>
  PIN IO_S<18>
    DIRECTION INOUT ;
    USE SIGNAL ;
    PORT
      LAYER METAL2 ;
        RECT 2704.1 217.55 2711.9 218.35 ;
    END
  END IO_S<18>
  PIN IO_S<17>
    DIRECTION INOUT ;
    USE SIGNAL ;
    PORT
      LAYER METAL2 ;
        RECT 2598.1 217.55 2605.9 218.35 ;
    END
  END IO_S<17>
  PIN IO_S<16>
    DIRECTION INOUT ;
    USE SIGNAL ;
    PORT
      LAYER METAL2 ;
        RECT 2492.1 217.55 2499.9 218.35 ;
    END
  END IO_S<16>
  PIN IO_S<15>
    DIRECTION INOUT ;
    USE SIGNAL ;
    PORT
      LAYER METAL2 ;
        RECT 2386.1 217.55 2393.9 218.35 ;
    END
  END IO_S<15>
  PIN IO_S<14>
    DIRECTION INOUT ;
    USE SIGNAL ;
    PORT
      LAYER METAL2 ;
        RECT 2280.1 217.55 2287.9 218.35 ;
    END
  END IO_S<14>
  PIN IO_S<13>
    DIRECTION INOUT ;
    USE SIGNAL ;
    PORT
      LAYER METAL2 ;
        RECT 2174.1 217.55 2181.9 218.35 ;
    END
  END IO_S<13>
  PIN IO_S<12>
    DIRECTION INOUT ;
    USE SIGNAL ;
    PORT
      LAYER METAL2 ;
        RECT 2068.1 217.55 2075.9 218.35 ;
    END
  END IO_S<12>
  PIN IO_S<11>
    DIRECTION INOUT ;
    USE SIGNAL ;
    PORT
      LAYER METAL2 ;
        RECT 1962.1 217.55 1969.9 218.35 ;
    END
  END IO_S<11>
  PIN IO_S<10>
    DIRECTION INOUT ;
    USE SIGNAL ;
    PORT
      LAYER METAL2 ;
        RECT 1856.1 217.55 1863.9 218.35 ;
    END
  END IO_S<10>
  PIN IO_S<9>
    DIRECTION INOUT ;
    USE SIGNAL ;
    PORT
      LAYER METAL2 ;
        RECT 1750.1 217.55 1757.9 218.35 ;
    END
  END IO_S<9>
  PIN IO_S<8>
    DIRECTION INOUT ;
    USE SIGNAL ;
    PORT
      LAYER METAL2 ;
        RECT 1644.1 217.55 1651.9 218.35 ;
    END
  END IO_S<8>
  PIN IO_S<7>
    DIRECTION INOUT ;
    USE SIGNAL ;
    PORT
      LAYER METAL2 ;
        RECT 1538.1 217.55 1545.9 218.35 ;
    END
  END IO_S<7>
  PIN IO_S<6>
    DIRECTION INOUT ;
    USE SIGNAL ;
    PORT
      LAYER METAL2 ;
        RECT 1432.1 217.55 1439.9 218.35 ;
    END
  END IO_S<6>
  PIN IO_S<5>
    DIRECTION INOUT ;
    USE SIGNAL ;
    PORT
      LAYER METAL2 ;
        RECT 1326.1 217.55 1333.9 218.35 ;
    END
  END IO_S<5>
  PIN IO_S<4>
    DIRECTION INOUT ;
    USE SIGNAL ;
    PORT
      LAYER METAL2 ;
        RECT 1220.1 217.55 1227.9 218.35 ;
    END
  END IO_S<4>
  PIN IO_S<3>
    DIRECTION INOUT ;
    USE SIGNAL ;
    PORT
      LAYER METAL2 ;
        RECT 1114.1 217.55 1121.9 218.35 ;
    END
  END IO_S<3>
  PIN IO_S<2>
    DIRECTION INOUT ;
    USE SIGNAL ;
    PORT
      LAYER METAL2 ;
        RECT 1008.1 217.55 1015.9 218.35 ;
    END
  END IO_S<2>
  PIN IO_S<1>
    DIRECTION INOUT ;
    USE SIGNAL ;
    PORT
      LAYER METAL2 ;
        RECT 902.1 217.55 909.9 218.35 ;
    END
  END IO_S<1>
  PIN IO_S<0>
    DIRECTION INOUT ;
    USE SIGNAL ;
    PORT
      LAYER METAL2 ;
        RECT 796.1 217.55 803.9 218.35 ;
    END
  END IO_S<0>
  PIN DVDD_S<0>
    DIRECTION INOUT ;
    USE SIGNAL ;
    PORT
      LAYER METAL2 ;
        RECT 690.1 217.55 697.9 218.35 ;
    END
  END DVDD_S<0>
  PIN DVDD_N<2>
    DIRECTION INOUT ;
    USE SIGNAL ;
    PORT
      LAYER METAL2 ;
        RECT 6626.1 1852.55 6633.9 1853.35 ;
    END
  END DVDD_N<2>
  PIN IO_N_CLK<3>
    DIRECTION INOUT ;
    USE SIGNAL ;
    PORT
      LAYER METAL2 ;
        RECT 6096.1 1852.55 6103.9 1853.35 ;
    END
  END IO_N_CLK<3>
  PIN IO_N<35>
    DIRECTION INOUT ;
    USE SIGNAL ;
    PORT
      LAYER METAL2 ;
        RECT 5884.1 1852.55 5891.9 1853.35 ;
    END
  END IO_N<35>
  PIN IO_N<34>
    DIRECTION INOUT ;
    USE SIGNAL ;
    PORT
      LAYER METAL2 ;
        RECT 5778.1 1852.55 5785.9 1853.35 ;
    END
  END IO_N<34>
  PIN IO_N<33>
    DIRECTION INOUT ;
    USE SIGNAL ;
    PORT
      LAYER METAL2 ;
        RECT 5672.1 1852.55 5679.9 1853.35 ;
    END
  END IO_N<33>
  PIN IO_N<32>
    DIRECTION INOUT ;
    USE SIGNAL ;
    PORT
      LAYER METAL2 ;
        RECT 5566.1 1852.55 5573.9 1853.35 ;
    END
  END IO_N<32>
  PIN IO_N<31>
    DIRECTION INOUT ;
    USE SIGNAL ;
    PORT
      LAYER METAL2 ;
        RECT 5460.1 1852.55 5467.9 1853.35 ;
    END
  END IO_N<31>
  PIN IO_N<30>
    DIRECTION INOUT ;
    USE SIGNAL ;
    PORT
      LAYER METAL2 ;
        RECT 5354.1 1852.55 5361.9 1853.35 ;
    END
  END IO_N<30>
  PIN IO_N<29>
    DIRECTION INOUT ;
    USE SIGNAL ;
    PORT
      LAYER METAL2 ;
        RECT 5248.1 1852.55 5255.9 1853.35 ;
    END
  END IO_N<29>
  PIN IO_N<28>
    DIRECTION INOUT ;
    USE SIGNAL ;
    PORT
      LAYER METAL2 ;
        RECT 5142.1 1852.55 5149.9 1853.35 ;
    END
  END IO_N<28>
  PIN IO_N<27>
    DIRECTION INOUT ;
    USE SIGNAL ;
    PORT
      LAYER METAL2 ;
        RECT 5036.1 1852.55 5043.9 1853.35 ;
    END
  END IO_N<27>
  PIN IO_N<26>
    DIRECTION INOUT ;
    USE SIGNAL ;
    PORT
      LAYER METAL2 ;
        RECT 4930.1 1852.55 4937.9 1853.35 ;
    END
  END IO_N<26>
  PIN IO_N<25>
    DIRECTION INOUT ;
    USE SIGNAL ;
    PORT
      LAYER METAL2 ;
        RECT 4824.1 1852.55 4831.9 1853.35 ;
    END
  END IO_N<25>
  PIN IO_N<24>
    DIRECTION INOUT ;
    USE SIGNAL ;
    PORT
      LAYER METAL2 ;
        RECT 4718.1 1852.55 4725.9 1853.35 ;
    END
  END IO_N<24>
  PIN IO_N<23>
    DIRECTION INOUT ;
    USE SIGNAL ;
    PORT
      LAYER METAL2 ;
        RECT 4612.1 1852.55 4619.9 1853.35 ;
    END
  END IO_N<23>
  PIN IO_N<22>
    DIRECTION INOUT ;
    USE SIGNAL ;
    PORT
      LAYER METAL2 ;
        RECT 4506.1 1852.55 4513.9 1853.35 ;
    END
  END IO_N<22>
  PIN IO_N<21>
    DIRECTION INOUT ;
    USE SIGNAL ;
    PORT
      LAYER METAL2 ;
        RECT 4400.1 1852.55 4407.9 1853.35 ;
    END
  END IO_N<21>
  PIN IO_N<20>
    DIRECTION INOUT ;
    USE SIGNAL ;
    PORT
      LAYER METAL2 ;
        RECT 4294.1 1852.55 4301.9 1853.35 ;
    END
  END IO_N<20>
  PIN IO_N<19>
    DIRECTION INOUT ;
    USE SIGNAL ;
    PORT
      LAYER METAL2 ;
        RECT 4188.1 1852.55 4195.9 1853.35 ;
    END
  END IO_N<19>
  PIN IO_N<18>
    DIRECTION INOUT ;
    USE SIGNAL ;
    PORT
      LAYER METAL2 ;
        RECT 4082.1 1852.55 4089.9 1853.35 ;
    END
  END IO_N<18>
  PIN IO_N_CLK<2>
    DIRECTION INOUT ;
    USE SIGNAL ;
    PORT
      LAYER METAL2 ;
        RECT 3870.1 1852.55 3877.9 1853.35 ;
    END
  END IO_N_CLK<2>
  PIN DVDD_N<1>
    DIRECTION INOUT ;
    USE SIGNAL ;
    PORT
      LAYER METAL2 ;
        RECT 3658.1 1852.55 3665.9 1853.35 ;
    END
  END DVDD_N<1>
  PIN IO_N_CLK<1>
    DIRECTION INOUT ;
    USE SIGNAL ;
    PORT
      LAYER METAL2 ;
        RECT 3128.1 1852.55 3135.9 1853.35 ;
    END
  END IO_N_CLK<1>
  PIN IO_N<17>
    DIRECTION INOUT ;
    USE SIGNAL ;
    PORT
      LAYER METAL2 ;
        RECT 2916.1 1852.55 2923.9 1853.35 ;
    END
  END IO_N<17>
  PIN IO_N<16>
    DIRECTION INOUT ;
    USE SIGNAL ;
    PORT
      LAYER METAL2 ;
        RECT 2810.1 1852.55 2817.9 1853.35 ;
    END
  END IO_N<16>
  PIN IO_N<15>
    DIRECTION INOUT ;
    USE SIGNAL ;
    PORT
      LAYER METAL2 ;
        RECT 2704.1 1852.55 2711.9 1853.35 ;
    END
  END IO_N<15>
  PIN IO_N<14>
    DIRECTION INOUT ;
    USE SIGNAL ;
    PORT
      LAYER METAL2 ;
        RECT 2598.1 1852.55 2605.9 1853.35 ;
    END
  END IO_N<14>
  PIN IO_N<13>
    DIRECTION INOUT ;
    USE SIGNAL ;
    PORT
      LAYER METAL2 ;
        RECT 2492.1 1852.55 2499.9 1853.35 ;
    END
  END IO_N<13>
  PIN IO_N<12>
    DIRECTION INOUT ;
    USE SIGNAL ;
    PORT
      LAYER METAL2 ;
        RECT 2386.1 1852.55 2393.9 1853.35 ;
    END
  END IO_N<12>
  PIN IO_N<11>
    DIRECTION INOUT ;
    USE SIGNAL ;
    PORT
      LAYER METAL2 ;
        RECT 2280.1 1852.55 2287.9 1853.35 ;
    END
  END IO_N<11>
  PIN IO_N<10>
    DIRECTION INOUT ;
    USE SIGNAL ;
    PORT
      LAYER METAL2 ;
        RECT 2174.1 1852.55 2181.9 1853.35 ;
    END
  END IO_N<10>
  PIN IO_N<9>
    DIRECTION INOUT ;
    USE SIGNAL ;
    PORT
      LAYER METAL2 ;
        RECT 2068.1 1852.55 2075.9 1853.35 ;
    END
  END IO_N<9>
  PIN IO_N<8>
    DIRECTION INOUT ;
    USE SIGNAL ;
    PORT
      LAYER METAL2 ;
        RECT 1962.1 1852.55 1969.9 1853.35 ;
    END
  END IO_N<8>
  PIN IO_N<7>
    DIRECTION INOUT ;
    USE SIGNAL ;
    PORT
      LAYER METAL2 ;
        RECT 1856.1 1852.55 1863.9 1853.35 ;
    END
  END IO_N<7>
  PIN IO_N<6>
    DIRECTION INOUT ;
    USE SIGNAL ;
    PORT
      LAYER METAL2 ;
        RECT 1750.1 1852.55 1757.9 1853.35 ;
    END
  END IO_N<6>
  PIN IO_N<5>
    DIRECTION INOUT ;
    USE SIGNAL ;
    PORT
      LAYER METAL2 ;
        RECT 1644.1 1852.55 1651.9 1853.35 ;
    END
  END IO_N<5>
  PIN IO_N<4>
    DIRECTION INOUT ;
    USE SIGNAL ;
    PORT
      LAYER METAL2 ;
        RECT 1538.1 1852.55 1545.9 1853.35 ;
    END
  END IO_N<4>
  PIN IO_N<3>
    DIRECTION INOUT ;
    USE SIGNAL ;
    PORT
      LAYER METAL2 ;
        RECT 1432.1 1852.55 1439.9 1853.35 ;
    END
  END IO_N<3>
  PIN IO_N<2>
    DIRECTION INOUT ;
    USE SIGNAL ;
    PORT
      LAYER METAL2 ;
        RECT 1326.1 1852.55 1333.9 1853.35 ;
    END
  END IO_N<2>
  PIN IO_N<1>
    DIRECTION INOUT ;
    USE SIGNAL ;
    PORT
      LAYER METAL2 ;
        RECT 1220.1 1852.55 1227.9 1853.35 ;
    END
  END IO_N<1>
  PIN IO_N<0>
    DIRECTION INOUT ;
    USE SIGNAL ;
    PORT
      LAYER METAL2 ;
        RECT 1114.1 1852.55 1121.9 1853.35 ;
    END
  END IO_N<0>
  PIN IO_N_CLK<0>
    DIRECTION INOUT ;
    USE SIGNAL ;
    PORT
      LAYER METAL2 ;
        RECT 902.1 1852.55 909.9 1853.35 ;
    END
  END IO_N_CLK<0>
  PIN DVDD_N<0>
    DIRECTION INOUT ;
    USE SIGNAL ;
    PORT
      LAYER METAL2 ;
        RECT 690.1 1852.55 697.9 1853.35 ;
    END
  END DVDD_N<0>
  PIN ESDVDD
    DIRECTION INOUT ;
    USE SIGNAL ;
    PORT
      LAYER METAL4 ;
        RECT 164.88 1878.77 167.15 1879.96 ;
    END
  END ESDVDD
  PIN AVDD
    DIRECTION INOUT ;
    USE SIGNAL ;
    PORT
      LAYER METAL4 ;
        RECT 187.75 1853.66 191.26 1855.73 ;
    END
  END AVDD
  PIN GND
    DIRECTION INOUT ;
    USE SIGNAL ;
    PORT
      LAYER METAL4 ;
        RECT 178.65 1862.13 183.27 1864.89 ;
    END
  END GND
  PIN VINJ
    DIRECTION INOUT ;
    USE SIGNAL ;
    PORT
      LAYER METAL4 ;
        RECT 170.25 1872.54 174.73 1875.85 ;
    END
  END VINJ
END frame_6p9mm_2mm_edit

END LIBRARY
